VERSION 5.8 ;
BUSBITCHARS "[]" ;
DIVIDERCHAR "/" ;
UNITS
    DATABASE MICRONS 1000 ;
END UNITS

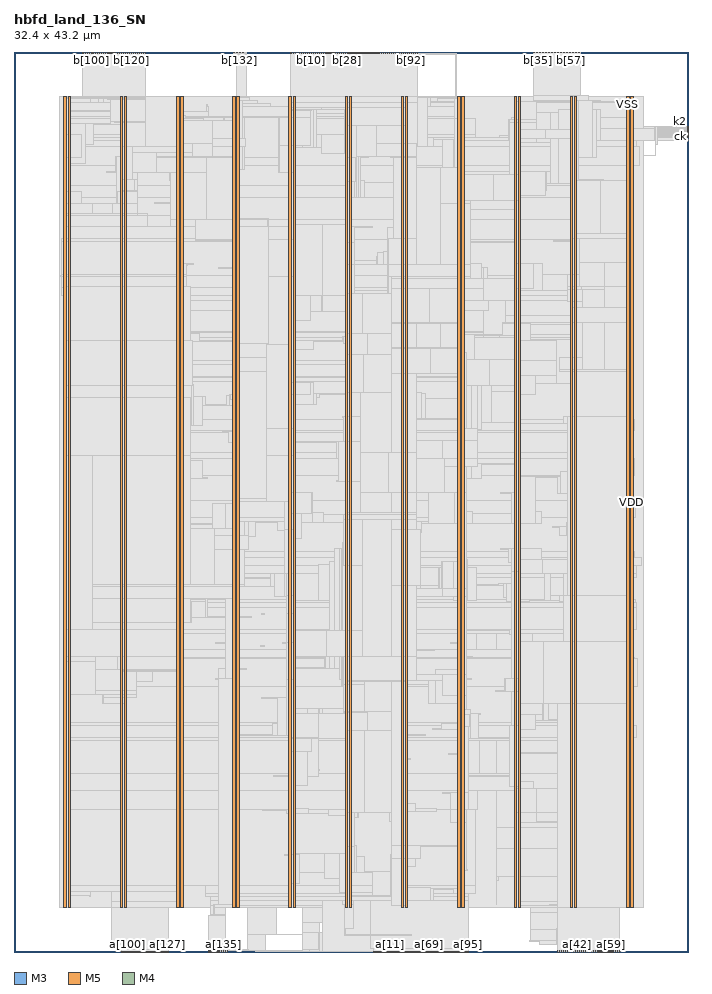
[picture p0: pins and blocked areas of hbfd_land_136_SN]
MACRO hbfd_land_136_SN
  FOREIGN hbfd_land_136_SN 0 0 ;
  CLASS BLOCK ;
  SIZE 32.4 BY 43.2 ;
  PIN a[0]
    DIRECTION INPUT ;
    USE SIGNAL ;
    PORT
      LAYER M3 ;
        RECT  17.244 0 17.262 0.037 ;
    END
  END a[0]
  PIN a[100]
    DIRECTION INPUT ;
    USE SIGNAL ;
    PORT
      LAYER M3 ;
        RECT  5.436 0 5.454 0.037 ;
    END
  END a[100]
  PIN a[101]
    DIRECTION INPUT ;
    USE SIGNAL ;
    PORT
      LAYER M3 ;
        RECT  5.508 0 5.526 0.037 ;
    END
  END a[101]
  PIN a[102]
    DIRECTION INPUT ;
    USE SIGNAL ;
    PORT
      LAYER M3 ;
        RECT  5.58 0 5.598 0.037 ;
    END
  END a[102]
  PIN a[103]
    DIRECTION INPUT ;
    USE SIGNAL ;
    PORT
      LAYER M3 ;
        RECT  5.652 0 5.67 0.037 ;
    END
  END a[103]
  PIN a[104]
    DIRECTION INPUT ;
    USE SIGNAL ;
    PORT
      LAYER M3 ;
        RECT  5.724 0 5.742 0.037 ;
    END
  END a[104]
  PIN a[105]
    DIRECTION INPUT ;
    USE SIGNAL ;
    PORT
      LAYER M3 ;
        RECT  5.796 0 5.814 0.037 ;
    END
  END a[105]
  PIN a[106]
    DIRECTION INPUT ;
    USE SIGNAL ;
    PORT
      LAYER M3 ;
        RECT  5.868 0 5.886 0.037 ;
    END
  END a[106]
  PIN a[107]
    DIRECTION INPUT ;
    USE SIGNAL ;
    PORT
      LAYER M3 ;
        RECT  5.94 0 5.958 0.037 ;
    END
  END a[107]
  PIN a[108]
    DIRECTION INPUT ;
    USE SIGNAL ;
    PORT
      LAYER M3 ;
        RECT  6.012 0 6.03 0.037 ;
    END
  END a[108]
  PIN a[109]
    DIRECTION INPUT ;
    USE SIGNAL ;
    PORT
      LAYER M3 ;
        RECT  6.084 0 6.102 0.037 ;
    END
  END a[109]
  PIN a[10]
    DIRECTION INPUT ;
    USE SIGNAL ;
    PORT
      LAYER M3 ;
        RECT  17.964 0 17.982 0.037 ;
    END
  END a[10]
  PIN a[110]
    DIRECTION INPUT ;
    USE SIGNAL ;
    PORT
      LAYER M3 ;
        RECT  6.156 0 6.174 0.037 ;
    END
  END a[110]
  PIN a[111]
    DIRECTION INPUT ;
    USE SIGNAL ;
    PORT
      LAYER M3 ;
        RECT  6.228 0 6.246 0.037 ;
    END
  END a[111]
  PIN a[112]
    DIRECTION INPUT ;
    USE SIGNAL ;
    PORT
      LAYER M3 ;
        RECT  6.3 0 6.318 0.037 ;
    END
  END a[112]
  PIN a[113]
    DIRECTION INPUT ;
    USE SIGNAL ;
    PORT
      LAYER M3 ;
        RECT  6.372 0 6.39 0.037 ;
    END
  END a[113]
  PIN a[114]
    DIRECTION INPUT ;
    USE SIGNAL ;
    PORT
      LAYER M3 ;
        RECT  6.444 0 6.462 0.037 ;
    END
  END a[114]
  PIN a[115]
    DIRECTION INPUT ;
    USE SIGNAL ;
    PORT
      LAYER M3 ;
        RECT  6.516 0 6.534 0.037 ;
    END
  END a[115]
  PIN a[116]
    DIRECTION INPUT ;
    USE SIGNAL ;
    PORT
      LAYER M3 ;
        RECT  6.588 0 6.606 0.037 ;
    END
  END a[116]
  PIN a[117]
    DIRECTION INPUT ;
    USE SIGNAL ;
    PORT
      LAYER M3 ;
        RECT  6.66 0 6.678 0.037 ;
    END
  END a[117]
  PIN a[118]
    DIRECTION INPUT ;
    USE SIGNAL ;
    PORT
      LAYER M3 ;
        RECT  6.732 0 6.75 0.037 ;
    END
  END a[118]
  PIN a[119]
    DIRECTION INPUT ;
    USE SIGNAL ;
    PORT
      LAYER M3 ;
        RECT  6.804 0 6.822 0.037 ;
    END
  END a[119]
  PIN a[11]
    DIRECTION INPUT ;
    USE SIGNAL ;
    PORT
      LAYER M3 ;
        RECT  18.036 0 18.054 0.037 ;
    END
  END a[11]
  PIN a[120]
    DIRECTION INPUT ;
    USE SIGNAL ;
    PORT
      LAYER M3 ;
        RECT  6.876 0 6.894 0.037 ;
    END
  END a[120]
  PIN a[121]
    DIRECTION INPUT ;
    USE SIGNAL ;
    PORT
      LAYER M3 ;
        RECT  6.948 0 6.966 0.037 ;
    END
  END a[121]
  PIN a[122]
    DIRECTION INPUT ;
    USE SIGNAL ;
    PORT
      LAYER M3 ;
        RECT  7.02 0 7.038 0.037 ;
    END
  END a[122]
  PIN a[123]
    DIRECTION INPUT ;
    USE SIGNAL ;
    PORT
      LAYER M3 ;
        RECT  7.092 0 7.11 0.037 ;
    END
  END a[123]
  PIN a[124]
    DIRECTION INPUT ;
    USE SIGNAL ;
    PORT
      LAYER M3 ;
        RECT  7.164 0 7.182 0.037 ;
    END
  END a[124]
  PIN a[125]
    DIRECTION INPUT ;
    USE SIGNAL ;
    PORT
      LAYER M3 ;
        RECT  7.236 0 7.254 0.037 ;
    END
  END a[125]
  PIN a[126]
    DIRECTION INPUT ;
    USE SIGNAL ;
    PORT
      LAYER M3 ;
        RECT  7.308 0 7.326 0.037 ;
    END
  END a[126]
  PIN a[127]
    DIRECTION INPUT ;
    USE SIGNAL ;
    PORT
      LAYER M3 ;
        RECT  7.38 0 7.398 0.037 ;
    END
  END a[127]
  PIN a[128]
    DIRECTION INPUT ;
    USE SIGNAL ;
    PORT
      LAYER M5 ;
        RECT  9.36 0 9.384 0.084 ;
    END
  END a[128]
  PIN a[129]
    DIRECTION INPUT ;
    USE SIGNAL ;
    PORT
      LAYER M5 ;
        RECT  9.456 0 9.48 0.084 ;
    END
  END a[129]
  PIN a[12]
    DIRECTION INPUT ;
    USE SIGNAL ;
    PORT
      LAYER M3 ;
        RECT  18.108 0 18.126 0.037 ;
    END
  END a[12]
  PIN a[130]
    DIRECTION INPUT ;
    USE SIGNAL ;
    PORT
      LAYER M5 ;
        RECT  9.552 0 9.576 0.084 ;
    END
  END a[130]
  PIN a[131]
    DIRECTION INPUT ;
    USE SIGNAL ;
    PORT
      LAYER M5 ;
        RECT  9.648 0 9.672 0.084 ;
    END
  END a[131]
  PIN a[132]
    DIRECTION INPUT ;
    USE SIGNAL ;
    PORT
      LAYER M5 ;
        RECT  9.744 0 9.768 0.084 ;
    END
  END a[132]
  PIN a[133]
    DIRECTION INPUT ;
    USE SIGNAL ;
    PORT
      LAYER M5 ;
        RECT  9.84 0 9.864 0.084 ;
    END
  END a[133]
  PIN a[134]
    DIRECTION INPUT ;
    USE SIGNAL ;
    PORT
      LAYER M5 ;
        RECT  9.936 0 9.96 0.084 ;
    END
  END a[134]
  PIN a[135]
    DIRECTION INPUT ;
    USE SIGNAL ;
    PORT
      LAYER M5 ;
        RECT  10.032 0 10.056 0.084 ;
    END
  END a[135]
  PIN a[13]
    DIRECTION INPUT ;
    USE SIGNAL ;
    PORT
      LAYER M3 ;
        RECT  18.18 0 18.198 0.037 ;
    END
  END a[13]
  PIN a[14]
    DIRECTION INPUT ;
    USE SIGNAL ;
    PORT
      LAYER M3 ;
        RECT  18.252 0 18.27 0.037 ;
    END
  END a[14]
  PIN a[15]
    DIRECTION INPUT ;
    USE SIGNAL ;
    PORT
      LAYER M3 ;
        RECT  18.324 0 18.342 0.037 ;
    END
  END a[15]
  PIN a[16]
    DIRECTION INPUT ;
    USE SIGNAL ;
    PORT
      LAYER M3 ;
        RECT  18.396 0 18.414 0.037 ;
    END
  END a[16]
  PIN a[17]
    DIRECTION INPUT ;
    USE SIGNAL ;
    PORT
      LAYER M3 ;
        RECT  18.468 0 18.486 0.037 ;
    END
  END a[17]
  PIN a[18]
    DIRECTION INPUT ;
    USE SIGNAL ;
    PORT
      LAYER M3 ;
        RECT  18.54 0 18.558 0.037 ;
    END
  END a[18]
  PIN a[19]
    DIRECTION INPUT ;
    USE SIGNAL ;
    PORT
      LAYER M3 ;
        RECT  18.612 0 18.63 0.037 ;
    END
  END a[19]
  PIN a[1]
    DIRECTION INPUT ;
    USE SIGNAL ;
    PORT
      LAYER M3 ;
        RECT  17.316 0 17.334 0.037 ;
    END
  END a[1]
  PIN a[20]
    DIRECTION INPUT ;
    USE SIGNAL ;
    PORT
      LAYER M3 ;
        RECT  18.684 0 18.702 0.037 ;
    END
  END a[20]
  PIN a[21]
    DIRECTION INPUT ;
    USE SIGNAL ;
    PORT
      LAYER M3 ;
        RECT  18.756 0 18.774 0.037 ;
    END
  END a[21]
  PIN a[22]
    DIRECTION INPUT ;
    USE SIGNAL ;
    PORT
      LAYER M3 ;
        RECT  18.828 0 18.846 0.037 ;
    END
  END a[22]
  PIN a[23]
    DIRECTION INPUT ;
    USE SIGNAL ;
    PORT
      LAYER M3 ;
        RECT  18.9 0 18.918 0.037 ;
    END
  END a[23]
  PIN a[24]
    DIRECTION INPUT ;
    USE SIGNAL ;
    PORT
      LAYER M3 ;
        RECT  18.972 0 18.99 0.037 ;
    END
  END a[24]
  PIN a[25]
    DIRECTION INPUT ;
    USE SIGNAL ;
    PORT
      LAYER M3 ;
        RECT  19.044 0 19.062 0.037 ;
    END
  END a[25]
  PIN a[26]
    DIRECTION INPUT ;
    USE SIGNAL ;
    PORT
      LAYER M3 ;
        RECT  19.116 0 19.134 0.037 ;
    END
  END a[26]
  PIN a[27]
    DIRECTION INPUT ;
    USE SIGNAL ;
    PORT
      LAYER M3 ;
        RECT  19.188 0 19.206 0.037 ;
    END
  END a[27]
  PIN a[28]
    DIRECTION INPUT ;
    USE SIGNAL ;
    PORT
      LAYER M3 ;
        RECT  19.26 0 19.278 0.037 ;
    END
  END a[28]
  PIN a[29]
    DIRECTION INPUT ;
    USE SIGNAL ;
    PORT
      LAYER M3 ;
        RECT  19.332 0 19.35 0.037 ;
    END
  END a[29]
  PIN a[2]
    DIRECTION INPUT ;
    USE SIGNAL ;
    PORT
      LAYER M3 ;
        RECT  17.388 0 17.406 0.037 ;
    END
  END a[2]
  PIN a[30]
    DIRECTION INPUT ;
    USE SIGNAL ;
    PORT
      LAYER M3 ;
        RECT  19.404 0 19.422 0.037 ;
    END
  END a[30]
  PIN a[31]
    DIRECTION INPUT ;
    USE SIGNAL ;
    PORT
      LAYER M3 ;
        RECT  19.476 0 19.494 0.037 ;
    END
  END a[31]
  PIN a[32]
    DIRECTION INPUT ;
    USE SIGNAL ;
    PORT
      LAYER M5 ;
        RECT  26.064 0 26.088 0.084 ;
    END
  END a[32]
  PIN a[33]
    DIRECTION INPUT ;
    USE SIGNAL ;
    PORT
      LAYER M5 ;
        RECT  26.16 0 26.184 0.084 ;
    END
  END a[33]
  PIN a[34]
    DIRECTION INPUT ;
    USE SIGNAL ;
    PORT
      LAYER M5 ;
        RECT  26.256 0 26.28 0.084 ;
    END
  END a[34]
  PIN a[35]
    DIRECTION INPUT ;
    USE SIGNAL ;
    PORT
      LAYER M5 ;
        RECT  26.352 0 26.376 0.084 ;
    END
  END a[35]
  PIN a[36]
    DIRECTION INPUT ;
    USE SIGNAL ;
    PORT
      LAYER M5 ;
        RECT  26.448 0 26.472 0.084 ;
    END
  END a[36]
  PIN a[37]
    DIRECTION INPUT ;
    USE SIGNAL ;
    PORT
      LAYER M5 ;
        RECT  26.544 0 26.568 0.084 ;
    END
  END a[37]
  PIN a[38]
    DIRECTION INPUT ;
    USE SIGNAL ;
    PORT
      LAYER M5 ;
        RECT  26.64 0 26.664 0.084 ;
    END
  END a[38]
  PIN a[39]
    DIRECTION INPUT ;
    USE SIGNAL ;
    PORT
      LAYER M5 ;
        RECT  26.736 0 26.76 0.084 ;
    END
  END a[39]
  PIN a[3]
    DIRECTION INPUT ;
    USE SIGNAL ;
    PORT
      LAYER M3 ;
        RECT  17.46 0 17.478 0.037 ;
    END
  END a[3]
  PIN a[40]
    DIRECTION INPUT ;
    USE SIGNAL ;
    PORT
      LAYER M5 ;
        RECT  26.832 0 26.856 0.084 ;
    END
  END a[40]
  PIN a[41]
    DIRECTION INPUT ;
    USE SIGNAL ;
    PORT
      LAYER M5 ;
        RECT  26.928 0 26.952 0.084 ;
    END
  END a[41]
  PIN a[42]
    DIRECTION INPUT ;
    USE SIGNAL ;
    PORT
      LAYER M5 ;
        RECT  27.024 0 27.048 0.084 ;
    END
  END a[42]
  PIN a[43]
    DIRECTION INPUT ;
    USE SIGNAL ;
    PORT
      LAYER M5 ;
        RECT  27.12 0 27.144 0.084 ;
    END
  END a[43]
  PIN a[44]
    DIRECTION INPUT ;
    USE SIGNAL ;
    PORT
      LAYER M5 ;
        RECT  27.216 0 27.24 0.084 ;
    END
  END a[44]
  PIN a[45]
    DIRECTION INPUT ;
    USE SIGNAL ;
    PORT
      LAYER M5 ;
        RECT  27.312 0 27.336 0.084 ;
    END
  END a[45]
  PIN a[46]
    DIRECTION INPUT ;
    USE SIGNAL ;
    PORT
      LAYER M5 ;
        RECT  27.408 0 27.432 0.084 ;
    END
  END a[46]
  PIN a[47]
    DIRECTION INPUT ;
    USE SIGNAL ;
    PORT
      LAYER M5 ;
        RECT  27.504 0 27.528 0.084 ;
    END
  END a[47]
  PIN a[48]
    DIRECTION INPUT ;
    USE SIGNAL ;
    PORT
      LAYER M5 ;
        RECT  27.6 0 27.624 0.084 ;
    END
  END a[48]
  PIN a[49]
    DIRECTION INPUT ;
    USE SIGNAL ;
    PORT
      LAYER M5 ;
        RECT  27.696 0 27.72 0.084 ;
    END
  END a[49]
  PIN a[4]
    DIRECTION INPUT ;
    USE SIGNAL ;
    PORT
      LAYER M3 ;
        RECT  17.532 0 17.55 0.037 ;
    END
  END a[4]
  PIN a[50]
    DIRECTION INPUT ;
    USE SIGNAL ;
    PORT
      LAYER M5 ;
        RECT  27.792 0 27.816 0.084 ;
    END
  END a[50]
  PIN a[51]
    DIRECTION INPUT ;
    USE SIGNAL ;
    PORT
      LAYER M5 ;
        RECT  27.888 0 27.912 0.084 ;
    END
  END a[51]
  PIN a[52]
    DIRECTION INPUT ;
    USE SIGNAL ;
    PORT
      LAYER M5 ;
        RECT  27.984 0 28.008 0.084 ;
    END
  END a[52]
  PIN a[53]
    DIRECTION INPUT ;
    USE SIGNAL ;
    PORT
      LAYER M5 ;
        RECT  28.08 0 28.104 0.084 ;
    END
  END a[53]
  PIN a[54]
    DIRECTION INPUT ;
    USE SIGNAL ;
    PORT
      LAYER M5 ;
        RECT  28.176 0 28.2 0.084 ;
    END
  END a[54]
  PIN a[55]
    DIRECTION INPUT ;
    USE SIGNAL ;
    PORT
      LAYER M5 ;
        RECT  28.272 0 28.296 0.084 ;
    END
  END a[55]
  PIN a[56]
    DIRECTION INPUT ;
    USE SIGNAL ;
    PORT
      LAYER M5 ;
        RECT  28.368 0 28.392 0.084 ;
    END
  END a[56]
  PIN a[57]
    DIRECTION INPUT ;
    USE SIGNAL ;
    PORT
      LAYER M5 ;
        RECT  28.464 0 28.488 0.084 ;
    END
  END a[57]
  PIN a[58]
    DIRECTION INPUT ;
    USE SIGNAL ;
    PORT
      LAYER M5 ;
        RECT  28.56 0 28.584 0.084 ;
    END
  END a[58]
  PIN a[59]
    DIRECTION INPUT ;
    USE SIGNAL ;
    PORT
      LAYER M5 ;
        RECT  28.656 0 28.68 0.084 ;
    END
  END a[59]
  PIN a[5]
    DIRECTION INPUT ;
    USE SIGNAL ;
    PORT
      LAYER M3 ;
        RECT  17.604 0 17.622 0.037 ;
    END
  END a[5]
  PIN a[60]
    DIRECTION INPUT ;
    USE SIGNAL ;
    PORT
      LAYER M5 ;
        RECT  28.752 0 28.776 0.084 ;
    END
  END a[60]
  PIN a[61]
    DIRECTION INPUT ;
    USE SIGNAL ;
    PORT
      LAYER M5 ;
        RECT  28.848 0 28.872 0.084 ;
    END
  END a[61]
  PIN a[62]
    DIRECTION INPUT ;
    USE SIGNAL ;
    PORT
      LAYER M5 ;
        RECT  28.944 0 28.968 0.084 ;
    END
  END a[62]
  PIN a[63]
    DIRECTION INPUT ;
    USE SIGNAL ;
    PORT
      LAYER M5 ;
        RECT  29.04 0 29.064 0.084 ;
    END
  END a[63]
  PIN a[64]
    DIRECTION INPUT ;
    USE SIGNAL ;
    PORT
      LAYER M3 ;
        RECT  19.548 0 19.566 0.037 ;
    END
  END a[64]
  PIN a[65]
    DIRECTION INPUT ;
    USE SIGNAL ;
    PORT
      LAYER M3 ;
        RECT  19.62 0 19.638 0.037 ;
    END
  END a[65]
  PIN a[66]
    DIRECTION INPUT ;
    USE SIGNAL ;
    PORT
      LAYER M3 ;
        RECT  19.692 0 19.71 0.037 ;
    END
  END a[66]
  PIN a[67]
    DIRECTION INPUT ;
    USE SIGNAL ;
    PORT
      LAYER M3 ;
        RECT  19.764 0 19.782 0.037 ;
    END
  END a[67]
  PIN a[68]
    DIRECTION INPUT ;
    USE SIGNAL ;
    PORT
      LAYER M3 ;
        RECT  19.836 0 19.854 0.037 ;
    END
  END a[68]
  PIN a[69]
    DIRECTION INPUT ;
    USE SIGNAL ;
    PORT
      LAYER M3 ;
        RECT  19.908 0 19.926 0.037 ;
    END
  END a[69]
  PIN a[6]
    DIRECTION INPUT ;
    USE SIGNAL ;
    PORT
      LAYER M3 ;
        RECT  17.676 0 17.694 0.037 ;
    END
  END a[6]
  PIN a[70]
    DIRECTION INPUT ;
    USE SIGNAL ;
    PORT
      LAYER M3 ;
        RECT  19.98 0 19.998 0.037 ;
    END
  END a[70]
  PIN a[71]
    DIRECTION INPUT ;
    USE SIGNAL ;
    PORT
      LAYER M3 ;
        RECT  20.052 0 20.07 0.037 ;
    END
  END a[71]
  PIN a[72]
    DIRECTION INPUT ;
    USE SIGNAL ;
    PORT
      LAYER M3 ;
        RECT  20.124 0 20.142 0.037 ;
    END
  END a[72]
  PIN a[73]
    DIRECTION INPUT ;
    USE SIGNAL ;
    PORT
      LAYER M3 ;
        RECT  20.196 0 20.214 0.037 ;
    END
  END a[73]
  PIN a[74]
    DIRECTION INPUT ;
    USE SIGNAL ;
    PORT
      LAYER M3 ;
        RECT  20.268 0 20.286 0.037 ;
    END
  END a[74]
  PIN a[75]
    DIRECTION INPUT ;
    USE SIGNAL ;
    PORT
      LAYER M3 ;
        RECT  20.34 0 20.358 0.037 ;
    END
  END a[75]
  PIN a[76]
    DIRECTION INPUT ;
    USE SIGNAL ;
    PORT
      LAYER M3 ;
        RECT  20.412 0 20.43 0.037 ;
    END
  END a[76]
  PIN a[77]
    DIRECTION INPUT ;
    USE SIGNAL ;
    PORT
      LAYER M3 ;
        RECT  20.484 0 20.502 0.037 ;
    END
  END a[77]
  PIN a[78]
    DIRECTION INPUT ;
    USE SIGNAL ;
    PORT
      LAYER M3 ;
        RECT  20.556 0 20.574 0.037 ;
    END
  END a[78]
  PIN a[79]
    DIRECTION INPUT ;
    USE SIGNAL ;
    PORT
      LAYER M3 ;
        RECT  20.628 0 20.646 0.037 ;
    END
  END a[79]
  PIN a[7]
    DIRECTION INPUT ;
    USE SIGNAL ;
    PORT
      LAYER M3 ;
        RECT  17.748 0 17.766 0.037 ;
    END
  END a[7]
  PIN a[80]
    DIRECTION INPUT ;
    USE SIGNAL ;
    PORT
      LAYER M3 ;
        RECT  20.7 0 20.718 0.037 ;
    END
  END a[80]
  PIN a[81]
    DIRECTION INPUT ;
    USE SIGNAL ;
    PORT
      LAYER M3 ;
        RECT  20.772 0 20.79 0.037 ;
    END
  END a[81]
  PIN a[82]
    DIRECTION INPUT ;
    USE SIGNAL ;
    PORT
      LAYER M3 ;
        RECT  20.844 0 20.862 0.037 ;
    END
  END a[82]
  PIN a[83]
    DIRECTION INPUT ;
    USE SIGNAL ;
    PORT
      LAYER M3 ;
        RECT  20.916 0 20.934 0.037 ;
    END
  END a[83]
  PIN a[84]
    DIRECTION INPUT ;
    USE SIGNAL ;
    PORT
      LAYER M3 ;
        RECT  20.988 0 21.006 0.037 ;
    END
  END a[84]
  PIN a[85]
    DIRECTION INPUT ;
    USE SIGNAL ;
    PORT
      LAYER M3 ;
        RECT  21.06 0 21.078 0.037 ;
    END
  END a[85]
  PIN a[86]
    DIRECTION INPUT ;
    USE SIGNAL ;
    PORT
      LAYER M3 ;
        RECT  21.132 0 21.15 0.037 ;
    END
  END a[86]
  PIN a[87]
    DIRECTION INPUT ;
    USE SIGNAL ;
    PORT
      LAYER M3 ;
        RECT  21.204 0 21.222 0.037 ;
    END
  END a[87]
  PIN a[88]
    DIRECTION INPUT ;
    USE SIGNAL ;
    PORT
      LAYER M3 ;
        RECT  21.276 0 21.294 0.037 ;
    END
  END a[88]
  PIN a[89]
    DIRECTION INPUT ;
    USE SIGNAL ;
    PORT
      LAYER M3 ;
        RECT  21.348 0 21.366 0.037 ;
    END
  END a[89]
  PIN a[8]
    DIRECTION INPUT ;
    USE SIGNAL ;
    PORT
      LAYER M3 ;
        RECT  17.82 0 17.838 0.037 ;
    END
  END a[8]
  PIN a[90]
    DIRECTION INPUT ;
    USE SIGNAL ;
    PORT
      LAYER M3 ;
        RECT  21.42 0 21.438 0.037 ;
    END
  END a[90]
  PIN a[91]
    DIRECTION INPUT ;
    USE SIGNAL ;
    PORT
      LAYER M3 ;
        RECT  21.492 0 21.51 0.037 ;
    END
  END a[91]
  PIN a[92]
    DIRECTION INPUT ;
    USE SIGNAL ;
    PORT
      LAYER M3 ;
        RECT  21.564 0 21.582 0.037 ;
    END
  END a[92]
  PIN a[93]
    DIRECTION INPUT ;
    USE SIGNAL ;
    PORT
      LAYER M3 ;
        RECT  21.636 0 21.654 0.037 ;
    END
  END a[93]
  PIN a[94]
    DIRECTION INPUT ;
    USE SIGNAL ;
    PORT
      LAYER M3 ;
        RECT  21.708 0 21.726 0.037 ;
    END
  END a[94]
  PIN a[95]
    DIRECTION INPUT ;
    USE SIGNAL ;
    PORT
      LAYER M3 ;
        RECT  21.78 0 21.798 0.037 ;
    END
  END a[95]
  PIN a[96]
    DIRECTION INPUT ;
    USE SIGNAL ;
    PORT
      LAYER M3 ;
        RECT  5.148 0 5.166 0.037 ;
    END
  END a[96]
  PIN a[97]
    DIRECTION INPUT ;
    USE SIGNAL ;
    PORT
      LAYER M3 ;
        RECT  5.22 0 5.238 0.037 ;
    END
  END a[97]
  PIN a[98]
    DIRECTION INPUT ;
    USE SIGNAL ;
    PORT
      LAYER M3 ;
        RECT  5.292 0 5.31 0.037 ;
    END
  END a[98]
  PIN a[99]
    DIRECTION INPUT ;
    USE SIGNAL ;
    PORT
      LAYER M3 ;
        RECT  5.364 0 5.382 0.037 ;
    END
  END a[99]
  PIN a[9]
    DIRECTION INPUT ;
    USE SIGNAL ;
    PORT
      LAYER M3 ;
        RECT  17.892 0 17.91 0.037 ;
    END
  END a[9]
  PIN b[0]
    DIRECTION OUTPUT ;
    USE SIGNAL ;
    PORT
      LAYER M5 ;
        RECT  13.296 43.116 13.32 43.2 ;
    END
  END b[0]
  PIN b[100]
    DIRECTION OUTPUT ;
    USE SIGNAL ;
    PORT
      LAYER M5 ;
        RECT  3.696 43.116 3.72 43.2 ;
    END
  END b[100]
  PIN b[101]
    DIRECTION OUTPUT ;
    USE SIGNAL ;
    PORT
      LAYER M5 ;
        RECT  3.792 43.116 3.816 43.2 ;
    END
  END b[101]
  PIN b[102]
    DIRECTION OUTPUT ;
    USE SIGNAL ;
    PORT
      LAYER M5 ;
        RECT  3.888 43.116 3.912 43.2 ;
    END
  END b[102]
  PIN b[103]
    DIRECTION OUTPUT ;
    USE SIGNAL ;
    PORT
      LAYER M5 ;
        RECT  3.984 43.116 4.008 43.2 ;
    END
  END b[103]
  PIN b[104]
    DIRECTION OUTPUT ;
    USE SIGNAL ;
    PORT
      LAYER M5 ;
        RECT  4.08 43.116 4.104 43.2 ;
    END
  END b[104]
  PIN b[105]
    DIRECTION OUTPUT ;
    USE SIGNAL ;
    PORT
      LAYER M5 ;
        RECT  4.176 43.116 4.2 43.2 ;
    END
  END b[105]
  PIN b[106]
    DIRECTION OUTPUT ;
    USE SIGNAL ;
    PORT
      LAYER M5 ;
        RECT  4.272 43.116 4.296 43.2 ;
    END
  END b[106]
  PIN b[107]
    DIRECTION OUTPUT ;
    USE SIGNAL ;
    PORT
      LAYER M5 ;
        RECT  4.368 43.116 4.392 43.2 ;
    END
  END b[107]
  PIN b[108]
    DIRECTION OUTPUT ;
    USE SIGNAL ;
    PORT
      LAYER M5 ;
        RECT  4.464 43.116 4.488 43.2 ;
    END
  END b[108]
  PIN b[109]
    DIRECTION OUTPUT ;
    USE SIGNAL ;
    PORT
      LAYER M5 ;
        RECT  4.56 43.116 4.584 43.2 ;
    END
  END b[109]
  PIN b[10]
    DIRECTION OUTPUT ;
    USE SIGNAL ;
    PORT
      LAYER M5 ;
        RECT  14.256 43.116 14.28 43.2 ;
    END
  END b[10]
  PIN b[110]
    DIRECTION OUTPUT ;
    USE SIGNAL ;
    PORT
      LAYER M5 ;
        RECT  4.656 43.116 4.68 43.2 ;
    END
  END b[110]
  PIN b[111]
    DIRECTION OUTPUT ;
    USE SIGNAL ;
    PORT
      LAYER M5 ;
        RECT  4.752 43.116 4.776 43.2 ;
    END
  END b[111]
  PIN b[112]
    DIRECTION OUTPUT ;
    USE SIGNAL ;
    PORT
      LAYER M5 ;
        RECT  4.848 43.116 4.872 43.2 ;
    END
  END b[112]
  PIN b[113]
    DIRECTION OUTPUT ;
    USE SIGNAL ;
    PORT
      LAYER M5 ;
        RECT  4.944 43.116 4.968 43.2 ;
    END
  END b[113]
  PIN b[114]
    DIRECTION OUTPUT ;
    USE SIGNAL ;
    PORT
      LAYER M5 ;
        RECT  5.04 43.116 5.064 43.2 ;
    END
  END b[114]
  PIN b[115]
    DIRECTION OUTPUT ;
    USE SIGNAL ;
    PORT
      LAYER M5 ;
        RECT  5.136 43.116 5.16 43.2 ;
    END
  END b[115]
  PIN b[116]
    DIRECTION OUTPUT ;
    USE SIGNAL ;
    PORT
      LAYER M5 ;
        RECT  5.232 43.116 5.256 43.2 ;
    END
  END b[116]
  PIN b[117]
    DIRECTION OUTPUT ;
    USE SIGNAL ;
    PORT
      LAYER M5 ;
        RECT  5.328 43.116 5.352 43.2 ;
    END
  END b[117]
  PIN b[118]
    DIRECTION OUTPUT ;
    USE SIGNAL ;
    PORT
      LAYER M5 ;
        RECT  5.424 43.116 5.448 43.2 ;
    END
  END b[118]
  PIN b[119]
    DIRECTION OUTPUT ;
    USE SIGNAL ;
    PORT
      LAYER M5 ;
        RECT  5.52 43.116 5.544 43.2 ;
    END
  END b[119]
  PIN b[11]
    DIRECTION OUTPUT ;
    USE SIGNAL ;
    PORT
      LAYER M5 ;
        RECT  14.352 43.116 14.376 43.2 ;
    END
  END b[11]
  PIN b[120]
    DIRECTION OUTPUT ;
    USE SIGNAL ;
    PORT
      LAYER M5 ;
        RECT  5.616 43.116 5.64 43.2 ;
    END
  END b[120]
  PIN b[121]
    DIRECTION OUTPUT ;
    USE SIGNAL ;
    PORT
      LAYER M5 ;
        RECT  5.712 43.116 5.736 43.2 ;
    END
  END b[121]
  PIN b[122]
    DIRECTION OUTPUT ;
    USE SIGNAL ;
    PORT
      LAYER M5 ;
        RECT  5.808 43.116 5.832 43.2 ;
    END
  END b[122]
  PIN b[123]
    DIRECTION OUTPUT ;
    USE SIGNAL ;
    PORT
      LAYER M5 ;
        RECT  5.904 43.116 5.928 43.2 ;
    END
  END b[123]
  PIN b[124]
    DIRECTION OUTPUT ;
    USE SIGNAL ;
    PORT
      LAYER M5 ;
        RECT  6 43.116 6.024 43.2 ;
    END
  END b[124]
  PIN b[125]
    DIRECTION OUTPUT ;
    USE SIGNAL ;
    PORT
      LAYER M5 ;
        RECT  6.096 43.116 6.12 43.2 ;
    END
  END b[125]
  PIN b[126]
    DIRECTION OUTPUT ;
    USE SIGNAL ;
    PORT
      LAYER M5 ;
        RECT  6.192 43.116 6.216 43.2 ;
    END
  END b[126]
  PIN b[127]
    DIRECTION OUTPUT ;
    USE SIGNAL ;
    PORT
      LAYER M5 ;
        RECT  6.288 43.116 6.312 43.2 ;
    END
  END b[127]
  PIN b[128]
    DIRECTION OUTPUT ;
    USE SIGNAL ;
    PORT
      LAYER M3 ;
        RECT  10.548 43.163 10.566 43.2 ;
    END
  END b[128]
  PIN b[129]
    DIRECTION OUTPUT ;
    USE SIGNAL ;
    PORT
      LAYER M3 ;
        RECT  10.62 43.163 10.638 43.2 ;
    END
  END b[129]
  PIN b[12]
    DIRECTION OUTPUT ;
    USE SIGNAL ;
    PORT
      LAYER M5 ;
        RECT  14.448 43.116 14.472 43.2 ;
    END
  END b[12]
  PIN b[130]
    DIRECTION OUTPUT ;
    USE SIGNAL ;
    PORT
      LAYER M3 ;
        RECT  10.692 43.163 10.71 43.2 ;
    END
  END b[130]
  PIN b[131]
    DIRECTION OUTPUT ;
    USE SIGNAL ;
    PORT
      LAYER M3 ;
        RECT  10.764 43.163 10.782 43.2 ;
    END
  END b[131]
  PIN b[132]
    DIRECTION OUTPUT ;
    USE SIGNAL ;
    PORT
      LAYER M3 ;
        RECT  10.836 43.163 10.854 43.2 ;
    END
  END b[132]
  PIN b[133]
    DIRECTION OUTPUT ;
    USE SIGNAL ;
    PORT
      LAYER M3 ;
        RECT  10.908 43.163 10.926 43.2 ;
    END
  END b[133]
  PIN b[134]
    DIRECTION OUTPUT ;
    USE SIGNAL ;
    PORT
      LAYER M3 ;
        RECT  10.98 43.163 10.998 43.2 ;
    END
  END b[134]
  PIN b[135]
    DIRECTION OUTPUT ;
    USE SIGNAL ;
    PORT
      LAYER M3 ;
        RECT  11.052 43.163 11.07 43.2 ;
    END
  END b[135]
  PIN b[13]
    DIRECTION OUTPUT ;
    USE SIGNAL ;
    PORT
      LAYER M5 ;
        RECT  14.544 43.116 14.568 43.2 ;
    END
  END b[13]
  PIN b[14]
    DIRECTION OUTPUT ;
    USE SIGNAL ;
    PORT
      LAYER M5 ;
        RECT  14.64 43.116 14.664 43.2 ;
    END
  END b[14]
  PIN b[15]
    DIRECTION OUTPUT ;
    USE SIGNAL ;
    PORT
      LAYER M5 ;
        RECT  14.736 43.116 14.76 43.2 ;
    END
  END b[15]
  PIN b[16]
    DIRECTION OUTPUT ;
    USE SIGNAL ;
    PORT
      LAYER M5 ;
        RECT  14.832 43.116 14.856 43.2 ;
    END
  END b[16]
  PIN b[17]
    DIRECTION OUTPUT ;
    USE SIGNAL ;
    PORT
      LAYER M5 ;
        RECT  14.928 43.116 14.952 43.2 ;
    END
  END b[17]
  PIN b[18]
    DIRECTION OUTPUT ;
    USE SIGNAL ;
    PORT
      LAYER M5 ;
        RECT  15.024 43.116 15.048 43.2 ;
    END
  END b[18]
  PIN b[19]
    DIRECTION OUTPUT ;
    USE SIGNAL ;
    PORT
      LAYER M5 ;
        RECT  15.12 43.116 15.144 43.2 ;
    END
  END b[19]
  PIN b[1]
    DIRECTION OUTPUT ;
    USE SIGNAL ;
    PORT
      LAYER M5 ;
        RECT  13.392 43.116 13.416 43.2 ;
    END
  END b[1]
  PIN b[20]
    DIRECTION OUTPUT ;
    USE SIGNAL ;
    PORT
      LAYER M5 ;
        RECT  15.216 43.116 15.24 43.2 ;
    END
  END b[20]
  PIN b[21]
    DIRECTION OUTPUT ;
    USE SIGNAL ;
    PORT
      LAYER M5 ;
        RECT  15.312 43.116 15.336 43.2 ;
    END
  END b[21]
  PIN b[22]
    DIRECTION OUTPUT ;
    USE SIGNAL ;
    PORT
      LAYER M5 ;
        RECT  15.408 43.116 15.432 43.2 ;
    END
  END b[22]
  PIN b[23]
    DIRECTION OUTPUT ;
    USE SIGNAL ;
    PORT
      LAYER M5 ;
        RECT  15.504 43.116 15.528 43.2 ;
    END
  END b[23]
  PIN b[24]
    DIRECTION OUTPUT ;
    USE SIGNAL ;
    PORT
      LAYER M5 ;
        RECT  15.6 43.116 15.624 43.2 ;
    END
  END b[24]
  PIN b[25]
    DIRECTION OUTPUT ;
    USE SIGNAL ;
    PORT
      LAYER M5 ;
        RECT  15.696 43.116 15.72 43.2 ;
    END
  END b[25]
  PIN b[26]
    DIRECTION OUTPUT ;
    USE SIGNAL ;
    PORT
      LAYER M5 ;
        RECT  15.792 43.116 15.816 43.2 ;
    END
  END b[26]
  PIN b[27]
    DIRECTION OUTPUT ;
    USE SIGNAL ;
    PORT
      LAYER M5 ;
        RECT  15.888 43.116 15.912 43.2 ;
    END
  END b[27]
  PIN b[28]
    DIRECTION OUTPUT ;
    USE SIGNAL ;
    PORT
      LAYER M5 ;
        RECT  15.984 43.116 16.008 43.2 ;
    END
  END b[28]
  PIN b[29]
    DIRECTION OUTPUT ;
    USE SIGNAL ;
    PORT
      LAYER M5 ;
        RECT  16.08 43.116 16.104 43.2 ;
    END
  END b[29]
  PIN b[2]
    DIRECTION OUTPUT ;
    USE SIGNAL ;
    PORT
      LAYER M5 ;
        RECT  13.488 43.116 13.512 43.2 ;
    END
  END b[2]
  PIN b[30]
    DIRECTION OUTPUT ;
    USE SIGNAL ;
    PORT
      LAYER M5 ;
        RECT  16.176 43.116 16.2 43.2 ;
    END
  END b[30]
  PIN b[31]
    DIRECTION OUTPUT ;
    USE SIGNAL ;
    PORT
      LAYER M5 ;
        RECT  16.272 43.116 16.296 43.2 ;
    END
  END b[31]
  PIN b[32]
    DIRECTION OUTPUT ;
    USE SIGNAL ;
    PORT
      LAYER M3 ;
        RECT  24.948 43.163 24.966 43.2 ;
    END
  END b[32]
  PIN b[33]
    DIRECTION OUTPUT ;
    USE SIGNAL ;
    PORT
      LAYER M3 ;
        RECT  25.02 43.163 25.038 43.2 ;
    END
  END b[33]
  PIN b[34]
    DIRECTION OUTPUT ;
    USE SIGNAL ;
    PORT
      LAYER M3 ;
        RECT  25.092 43.163 25.11 43.2 ;
    END
  END b[34]
  PIN b[35]
    DIRECTION OUTPUT ;
    USE SIGNAL ;
    PORT
      LAYER M3 ;
        RECT  25.164 43.163 25.182 43.2 ;
    END
  END b[35]
  PIN b[36]
    DIRECTION OUTPUT ;
    USE SIGNAL ;
    PORT
      LAYER M3 ;
        RECT  25.236 43.163 25.254 43.2 ;
    END
  END b[36]
  PIN b[37]
    DIRECTION OUTPUT ;
    USE SIGNAL ;
    PORT
      LAYER M3 ;
        RECT  25.308 43.163 25.326 43.2 ;
    END
  END b[37]
  PIN b[38]
    DIRECTION OUTPUT ;
    USE SIGNAL ;
    PORT
      LAYER M3 ;
        RECT  25.38 43.163 25.398 43.2 ;
    END
  END b[38]
  PIN b[39]
    DIRECTION OUTPUT ;
    USE SIGNAL ;
    PORT
      LAYER M3 ;
        RECT  25.452 43.163 25.47 43.2 ;
    END
  END b[39]
  PIN b[3]
    DIRECTION OUTPUT ;
    USE SIGNAL ;
    PORT
      LAYER M5 ;
        RECT  13.584 43.116 13.608 43.2 ;
    END
  END b[3]
  PIN b[40]
    DIRECTION OUTPUT ;
    USE SIGNAL ;
    PORT
      LAYER M3 ;
        RECT  25.524 43.163 25.542 43.2 ;
    END
  END b[40]
  PIN b[41]
    DIRECTION OUTPUT ;
    USE SIGNAL ;
    PORT
      LAYER M3 ;
        RECT  25.596 43.163 25.614 43.2 ;
    END
  END b[41]
  PIN b[42]
    DIRECTION OUTPUT ;
    USE SIGNAL ;
    PORT
      LAYER M3 ;
        RECT  25.668 43.163 25.686 43.2 ;
    END
  END b[42]
  PIN b[43]
    DIRECTION OUTPUT ;
    USE SIGNAL ;
    PORT
      LAYER M3 ;
        RECT  25.74 43.163 25.758 43.2 ;
    END
  END b[43]
  PIN b[44]
    DIRECTION OUTPUT ;
    USE SIGNAL ;
    PORT
      LAYER M3 ;
        RECT  25.812 43.163 25.83 43.2 ;
    END
  END b[44]
  PIN b[45]
    DIRECTION OUTPUT ;
    USE SIGNAL ;
    PORT
      LAYER M3 ;
        RECT  25.884 43.163 25.902 43.2 ;
    END
  END b[45]
  PIN b[46]
    DIRECTION OUTPUT ;
    USE SIGNAL ;
    PORT
      LAYER M3 ;
        RECT  25.956 43.163 25.974 43.2 ;
    END
  END b[46]
  PIN b[47]
    DIRECTION OUTPUT ;
    USE SIGNAL ;
    PORT
      LAYER M3 ;
        RECT  26.028 43.163 26.046 43.2 ;
    END
  END b[47]
  PIN b[48]
    DIRECTION OUTPUT ;
    USE SIGNAL ;
    PORT
      LAYER M3 ;
        RECT  26.1 43.163 26.118 43.2 ;
    END
  END b[48]
  PIN b[49]
    DIRECTION OUTPUT ;
    USE SIGNAL ;
    PORT
      LAYER M3 ;
        RECT  26.172 43.163 26.19 43.2 ;
    END
  END b[49]
  PIN b[4]
    DIRECTION OUTPUT ;
    USE SIGNAL ;
    PORT
      LAYER M5 ;
        RECT  13.68 43.116 13.704 43.2 ;
    END
  END b[4]
  PIN b[50]
    DIRECTION OUTPUT ;
    USE SIGNAL ;
    PORT
      LAYER M3 ;
        RECT  26.244 43.163 26.262 43.2 ;
    END
  END b[50]
  PIN b[51]
    DIRECTION OUTPUT ;
    USE SIGNAL ;
    PORT
      LAYER M3 ;
        RECT  26.316 43.163 26.334 43.2 ;
    END
  END b[51]
  PIN b[52]
    DIRECTION OUTPUT ;
    USE SIGNAL ;
    PORT
      LAYER M3 ;
        RECT  26.388 43.163 26.406 43.2 ;
    END
  END b[52]
  PIN b[53]
    DIRECTION OUTPUT ;
    USE SIGNAL ;
    PORT
      LAYER M3 ;
        RECT  26.46 43.163 26.478 43.2 ;
    END
  END b[53]
  PIN b[54]
    DIRECTION OUTPUT ;
    USE SIGNAL ;
    PORT
      LAYER M3 ;
        RECT  26.532 43.163 26.55 43.2 ;
    END
  END b[54]
  PIN b[55]
    DIRECTION OUTPUT ;
    USE SIGNAL ;
    PORT
      LAYER M3 ;
        RECT  26.604 43.163 26.622 43.2 ;
    END
  END b[55]
  PIN b[56]
    DIRECTION OUTPUT ;
    USE SIGNAL ;
    PORT
      LAYER M3 ;
        RECT  26.676 43.163 26.694 43.2 ;
    END
  END b[56]
  PIN b[57]
    DIRECTION OUTPUT ;
    USE SIGNAL ;
    PORT
      LAYER M3 ;
        RECT  26.748 43.163 26.766 43.2 ;
    END
  END b[57]
  PIN b[58]
    DIRECTION OUTPUT ;
    USE SIGNAL ;
    PORT
      LAYER M3 ;
        RECT  26.82 43.163 26.838 43.2 ;
    END
  END b[58]
  PIN b[59]
    DIRECTION OUTPUT ;
    USE SIGNAL ;
    PORT
      LAYER M3 ;
        RECT  26.892 43.163 26.91 43.2 ;
    END
  END b[59]
  PIN b[5]
    DIRECTION OUTPUT ;
    USE SIGNAL ;
    PORT
      LAYER M5 ;
        RECT  13.776 43.116 13.8 43.2 ;
    END
  END b[5]
  PIN b[60]
    DIRECTION OUTPUT ;
    USE SIGNAL ;
    PORT
      LAYER M3 ;
        RECT  26.964 43.163 26.982 43.2 ;
    END
  END b[60]
  PIN b[61]
    DIRECTION OUTPUT ;
    USE SIGNAL ;
    PORT
      LAYER M3 ;
        RECT  27.036 43.163 27.054 43.2 ;
    END
  END b[61]
  PIN b[62]
    DIRECTION OUTPUT ;
    USE SIGNAL ;
    PORT
      LAYER M3 ;
        RECT  27.108 43.163 27.126 43.2 ;
    END
  END b[62]
  PIN b[63]
    DIRECTION OUTPUT ;
    USE SIGNAL ;
    PORT
      LAYER M3 ;
        RECT  27.18 43.163 27.198 43.2 ;
    END
  END b[63]
  PIN b[64]
    DIRECTION OUTPUT ;
    USE SIGNAL ;
    PORT
      LAYER M5 ;
        RECT  16.368 43.116 16.392 43.2 ;
    END
  END b[64]
  PIN b[65]
    DIRECTION OUTPUT ;
    USE SIGNAL ;
    PORT
      LAYER M5 ;
        RECT  16.464 43.116 16.488 43.2 ;
    END
  END b[65]
  PIN b[66]
    DIRECTION OUTPUT ;
    USE SIGNAL ;
    PORT
      LAYER M5 ;
        RECT  16.56 43.116 16.584 43.2 ;
    END
  END b[66]
  PIN b[67]
    DIRECTION OUTPUT ;
    USE SIGNAL ;
    PORT
      LAYER M5 ;
        RECT  16.656 43.116 16.68 43.2 ;
    END
  END b[67]
  PIN b[68]
    DIRECTION OUTPUT ;
    USE SIGNAL ;
    PORT
      LAYER M5 ;
        RECT  16.752 43.116 16.776 43.2 ;
    END
  END b[68]
  PIN b[69]
    DIRECTION OUTPUT ;
    USE SIGNAL ;
    PORT
      LAYER M5 ;
        RECT  16.848 43.116 16.872 43.2 ;
    END
  END b[69]
  PIN b[6]
    DIRECTION OUTPUT ;
    USE SIGNAL ;
    PORT
      LAYER M5 ;
        RECT  13.872 43.116 13.896 43.2 ;
    END
  END b[6]
  PIN b[70]
    DIRECTION OUTPUT ;
    USE SIGNAL ;
    PORT
      LAYER M5 ;
        RECT  16.944 43.116 16.968 43.2 ;
    END
  END b[70]
  PIN b[71]
    DIRECTION OUTPUT ;
    USE SIGNAL ;
    PORT
      LAYER M5 ;
        RECT  17.04 43.116 17.064 43.2 ;
    END
  END b[71]
  PIN b[72]
    DIRECTION OUTPUT ;
    USE SIGNAL ;
    PORT
      LAYER M5 ;
        RECT  17.136 43.116 17.16 43.2 ;
    END
  END b[72]
  PIN b[73]
    DIRECTION OUTPUT ;
    USE SIGNAL ;
    PORT
      LAYER M5 ;
        RECT  17.232 43.116 17.256 43.2 ;
    END
  END b[73]
  PIN b[74]
    DIRECTION OUTPUT ;
    USE SIGNAL ;
    PORT
      LAYER M5 ;
        RECT  17.328 43.116 17.352 43.2 ;
    END
  END b[74]
  PIN b[75]
    DIRECTION OUTPUT ;
    USE SIGNAL ;
    PORT
      LAYER M5 ;
        RECT  17.424 43.116 17.448 43.2 ;
    END
  END b[75]
  PIN b[76]
    DIRECTION OUTPUT ;
    USE SIGNAL ;
    PORT
      LAYER M5 ;
        RECT  17.52 43.116 17.544 43.2 ;
    END
  END b[76]
  PIN b[77]
    DIRECTION OUTPUT ;
    USE SIGNAL ;
    PORT
      LAYER M5 ;
        RECT  17.616 43.116 17.64 43.2 ;
    END
  END b[77]
  PIN b[78]
    DIRECTION OUTPUT ;
    USE SIGNAL ;
    PORT
      LAYER M5 ;
        RECT  17.712 43.116 17.736 43.2 ;
    END
  END b[78]
  PIN b[79]
    DIRECTION OUTPUT ;
    USE SIGNAL ;
    PORT
      LAYER M5 ;
        RECT  17.808 43.116 17.832 43.2 ;
    END
  END b[79]
  PIN b[7]
    DIRECTION OUTPUT ;
    USE SIGNAL ;
    PORT
      LAYER M5 ;
        RECT  13.968 43.116 13.992 43.2 ;
    END
  END b[7]
  PIN b[80]
    DIRECTION OUTPUT ;
    USE SIGNAL ;
    PORT
      LAYER M5 ;
        RECT  17.904 43.116 17.928 43.2 ;
    END
  END b[80]
  PIN b[81]
    DIRECTION OUTPUT ;
    USE SIGNAL ;
    PORT
      LAYER M5 ;
        RECT  18 43.116 18.024 43.2 ;
    END
  END b[81]
  PIN b[82]
    DIRECTION OUTPUT ;
    USE SIGNAL ;
    PORT
      LAYER M5 ;
        RECT  18.096 43.116 18.12 43.2 ;
    END
  END b[82]
  PIN b[83]
    DIRECTION OUTPUT ;
    USE SIGNAL ;
    PORT
      LAYER M5 ;
        RECT  18.192 43.116 18.216 43.2 ;
    END
  END b[83]
  PIN b[84]
    DIRECTION OUTPUT ;
    USE SIGNAL ;
    PORT
      LAYER M5 ;
        RECT  18.288 43.116 18.312 43.2 ;
    END
  END b[84]
  PIN b[85]
    DIRECTION OUTPUT ;
    USE SIGNAL ;
    PORT
      LAYER M5 ;
        RECT  18.384 43.116 18.408 43.2 ;
    END
  END b[85]
  PIN b[86]
    DIRECTION OUTPUT ;
    USE SIGNAL ;
    PORT
      LAYER M5 ;
        RECT  18.48 43.116 18.504 43.2 ;
    END
  END b[86]
  PIN b[87]
    DIRECTION OUTPUT ;
    USE SIGNAL ;
    PORT
      LAYER M5 ;
        RECT  18.576 43.116 18.6 43.2 ;
    END
  END b[87]
  PIN b[88]
    DIRECTION OUTPUT ;
    USE SIGNAL ;
    PORT
      LAYER M5 ;
        RECT  18.672 43.116 18.696 43.2 ;
    END
  END b[88]
  PIN b[89]
    DIRECTION OUTPUT ;
    USE SIGNAL ;
    PORT
      LAYER M5 ;
        RECT  18.768 43.116 18.792 43.2 ;
    END
  END b[89]
  PIN b[8]
    DIRECTION OUTPUT ;
    USE SIGNAL ;
    PORT
      LAYER M5 ;
        RECT  14.064 43.116 14.088 43.2 ;
    END
  END b[8]
  PIN b[90]
    DIRECTION OUTPUT ;
    USE SIGNAL ;
    PORT
      LAYER M5 ;
        RECT  18.864 43.116 18.888 43.2 ;
    END
  END b[90]
  PIN b[91]
    DIRECTION OUTPUT ;
    USE SIGNAL ;
    PORT
      LAYER M5 ;
        RECT  18.96 43.116 18.984 43.2 ;
    END
  END b[91]
  PIN b[92]
    DIRECTION OUTPUT ;
    USE SIGNAL ;
    PORT
      LAYER M5 ;
        RECT  19.056 43.116 19.08 43.2 ;
    END
  END b[92]
  PIN b[93]
    DIRECTION OUTPUT ;
    USE SIGNAL ;
    PORT
      LAYER M5 ;
        RECT  19.152 43.116 19.176 43.2 ;
    END
  END b[93]
  PIN b[94]
    DIRECTION OUTPUT ;
    USE SIGNAL ;
    PORT
      LAYER M5 ;
        RECT  19.248 43.116 19.272 43.2 ;
    END
  END b[94]
  PIN b[95]
    DIRECTION OUTPUT ;
    USE SIGNAL ;
    PORT
      LAYER M5 ;
        RECT  19.344 43.116 19.368 43.2 ;
    END
  END b[95]
  PIN b[96]
    DIRECTION OUTPUT ;
    USE SIGNAL ;
    PORT
      LAYER M5 ;
        RECT  3.312 43.116 3.336 43.2 ;
    END
  END b[96]
  PIN b[97]
    DIRECTION OUTPUT ;
    USE SIGNAL ;
    PORT
      LAYER M5 ;
        RECT  3.408 43.116 3.432 43.2 ;
    END
  END b[97]
  PIN b[98]
    DIRECTION OUTPUT ;
    USE SIGNAL ;
    PORT
      LAYER M5 ;
        RECT  3.504 43.116 3.528 43.2 ;
    END
  END b[98]
  PIN b[99]
    DIRECTION OUTPUT ;
    USE SIGNAL ;
    PORT
      LAYER M5 ;
        RECT  3.6 43.116 3.624 43.2 ;
    END
  END b[99]
  PIN b[9]
    DIRECTION OUTPUT ;
    USE SIGNAL ;
    PORT
      LAYER M5 ;
        RECT  14.16 43.116 14.184 43.2 ;
    END
  END b[9]
  PIN ck
    DIRECTION INPUT ;
    USE SIGNAL ;
    PORT
      LAYER M4 ;
        RECT  32.316 39.12 32.4 39.144 ;
    END
  END ck
  PIN ckf
    DIRECTION INPUT ;
    USE SIGNAL ;
    PORT
      LAYER M5 ;
        RECT  10.128 0 10.152 0.084 ;
    END
  END ckf
  PIN ea
    DIRECTION INPUT ;
    USE SIGNAL ;
    PORT
      LAYER M5 ;
        RECT  10.224 0 10.248 0.084 ;
    END
  END ea
  PIN fault
    DIRECTION OUTPUT ;
    USE SIGNAL ;
    PORT
      LAYER M4 ;
        RECT  32.316 39.216 32.4 39.24 ;
    END
  END fault
  PIN k0
    DIRECTION INPUT ;
    USE SIGNAL ;
    PORT
      LAYER M4 ;
        RECT  32.316 39.312 32.4 39.336 ;
    END
  END k0
  PIN k1
    DIRECTION INPUT ;
    USE SIGNAL ;
    PORT
      LAYER M4 ;
        RECT  32.316 39.408 32.4 39.432 ;
    END
  END k1
  PIN k2
    DIRECTION INPUT ;
    USE SIGNAL ;
    PORT
      LAYER M4 ;
        RECT  32.316 39.504 32.4 39.528 ;
    END
  END k2
  PIN rs
    DIRECTION INPUT ;
    USE SIGNAL ;
    PORT
      LAYER M4 ;
        RECT  32.316 39.6 32.4 39.624 ;
    END
  END rs
  PIN VDD
    DIRECTION INOUT ;
    USE POWER ;
    PORT
      LAYER M5 ;
        RECT  29.592 2.151 29.712 41.049 ;
        RECT  26.892 2.151 27.012 41.049 ;
        RECT  24.192 2.151 24.312 41.049 ;
        RECT  21.492 2.151 21.612 41.049 ;
        RECT  18.792 2.151 18.912 41.049 ;
        RECT  16.092 2.151 16.212 41.049 ;
        RECT  13.392 2.151 13.512 41.049 ;
        RECT  10.692 2.151 10.812 41.049 ;
        RECT  7.992 2.151 8.112 41.049 ;
        RECT  5.292 2.151 5.412 41.049 ;
        RECT  2.592 2.151 2.712 41.049 ;
    END
  END VDD
  PIN VSS
    DIRECTION INOUT ;
    USE GROUND ;
    PORT
      LAYER M5 ;
        RECT  29.4 2.137 29.52 41.063 ;
        RECT  26.7 2.137 26.82 41.063 ;
        RECT  24 2.137 24.12 41.063 ;
        RECT  21.3 2.137 21.42 41.063 ;
        RECT  18.6 2.137 18.72 41.063 ;
        RECT  15.9 2.137 16.02 41.063 ;
        RECT  13.2 2.137 13.32 41.063 ;
        RECT  10.5 2.137 10.62 41.063 ;
        RECT  7.8 2.137 7.92 41.063 ;
        RECT  5.1 2.137 5.22 41.063 ;
        RECT  2.4 2.137 2.52 41.063 ;
    END
  END VSS
  # OT_OBS_CLOSED layer=M5 d_um=1.536 added=79
  OBS
    LAYER RVTN ;
     RECT  2.16 2.16 30.24 2.295 ;
     RECT  2.16 2.565 30.24 2.835 ;
     RECT  2.16 3.105 30.24 3.375 ;
     RECT  2.16 3.645 30.24 3.915 ;
     RECT  2.16 4.185 30.24 4.455 ;
     RECT  2.16 4.725 30.24 4.995 ;
     RECT  2.16 5.265 30.24 5.535 ;
     RECT  2.16 5.805 30.24 6.075 ;
     RECT  2.16 6.345 30.24 6.615 ;
     RECT  2.16 6.885 30.24 7.155 ;
     RECT  2.16 7.425 30.24 7.695 ;
     RECT  2.16 7.965 30.24 8.235 ;
     RECT  2.16 8.505 30.24 8.775 ;
     RECT  2.16 9.045 30.24 9.315 ;
     RECT  2.16 9.585 30.24 9.855 ;
     RECT  2.16 10.125 30.24 10.395 ;
     RECT  2.16 10.665 30.24 10.935 ;
     RECT  2.16 11.205 30.24 11.475 ;
     RECT  2.16 11.745 30.24 12.015 ;
     RECT  2.16 12.285 30.24 12.555 ;
     RECT  2.16 12.825 30.24 13.095 ;
     RECT  2.16 13.365 30.24 13.635 ;
     RECT  2.16 13.905 30.24 14.175 ;
     RECT  2.16 14.445 30.24 14.715 ;
     RECT  2.16 14.985 30.24 15.255 ;
     RECT  2.16 15.525 30.24 15.795 ;
     RECT  2.16 16.065 30.24 16.335 ;
     RECT  2.16 16.605 30.24 16.875 ;
     RECT  2.16 17.145 30.24 17.415 ;
     RECT  2.16 17.685 30.24 17.955 ;
     RECT  2.16 18.225 30.24 18.495 ;
     RECT  2.16 18.765 30.24 19.035 ;
     RECT  2.16 19.305 30.24 19.575 ;
     RECT  2.16 19.845 30.24 20.115 ;
     RECT  2.16 20.385 30.24 20.655 ;
     RECT  2.16 20.925 30.24 21.195 ;
     RECT  2.16 21.465 30.24 21.735 ;
     RECT  2.16 22.005 30.24 22.275 ;
     RECT  2.16 22.545 30.24 22.815 ;
     RECT  2.16 23.085 30.24 23.355 ;
     RECT  2.16 23.625 30.24 23.895 ;
     RECT  2.16 24.165 30.24 24.435 ;
     RECT  2.16 24.705 30.24 24.975 ;
     RECT  2.16 25.245 30.24 25.515 ;
     RECT  2.16 25.785 30.24 26.055 ;
     RECT  2.16 26.325 30.24 26.595 ;
     RECT  2.16 26.865 30.24 27.135 ;
     RECT  2.16 27.405 30.24 27.675 ;
     RECT  2.16 27.945 30.24 28.215 ;
     RECT  2.16 28.485 30.24 28.755 ;
     RECT  2.16 29.025 30.24 29.295 ;
     RECT  2.16 29.565 30.24 29.835 ;
     RECT  2.16 30.105 30.24 30.375 ;
     RECT  2.16 30.645 30.24 30.915 ;
     RECT  2.16 31.185 30.24 31.455 ;
     RECT  2.16 31.725 30.24 31.995 ;
     RECT  2.16 32.265 30.24 32.535 ;
     RECT  2.16 32.805 30.24 33.075 ;
     RECT  2.16 33.345 30.24 33.615 ;
     RECT  2.16 33.885 30.24 34.155 ;
     RECT  2.16 34.425 30.24 34.695 ;
     RECT  2.16 34.965 30.24 35.235 ;
     RECT  2.16 35.505 30.24 35.775 ;
     RECT  2.16 36.045 30.24 36.315 ;
     RECT  2.16 36.585 30.24 36.855 ;
     RECT  2.16 37.125 30.24 37.395 ;
     RECT  2.16 37.665 30.24 37.935 ;
     RECT  2.16 38.205 30.24 38.475 ;
     RECT  2.16 38.745 30.24 39.015 ;
     RECT  2.16 39.285 30.24 39.555 ;
     RECT  2.16 39.825 30.24 40.095 ;
     RECT  2.16 40.365 30.24 40.635 ;
     RECT  2.16 40.905 30.24 41.04 ;
    LAYER RVTP ;
     RECT  2.16 2.295 30.24 2.565 ;
     RECT  2.16 2.835 30.24 3.105 ;
     RECT  2.16 3.375 30.24 3.645 ;
     RECT  2.16 3.915 30.24 4.185 ;
     RECT  2.16 4.455 30.24 4.725 ;
     RECT  2.16 4.995 30.24 5.265 ;
     RECT  2.16 5.535 30.24 5.805 ;
     RECT  2.16 6.075 30.24 6.345 ;
     RECT  2.16 6.615 30.24 6.885 ;
     RECT  2.16 7.155 30.24 7.425 ;
     RECT  2.16 7.695 30.24 7.965 ;
     RECT  2.16 8.235 30.24 8.505 ;
     RECT  2.16 8.775 30.24 9.045 ;
     RECT  2.16 9.315 30.24 9.585 ;
     RECT  2.16 9.855 30.24 10.125 ;
     RECT  2.16 10.395 30.24 10.665 ;
     RECT  2.16 10.935 30.24 11.205 ;
     RECT  2.16 11.475 30.24 11.745 ;
     RECT  2.16 12.015 30.24 12.285 ;
     RECT  2.16 12.555 30.24 12.825 ;
     RECT  2.16 13.095 30.24 13.365 ;
     RECT  2.16 13.635 30.24 13.905 ;
     RECT  2.16 14.175 30.24 14.445 ;
     RECT  2.16 14.715 30.24 14.985 ;
     RECT  2.16 15.255 30.24 15.525 ;
     RECT  2.16 15.795 30.24 16.065 ;
     RECT  2.16 16.335 30.24 16.605 ;
     RECT  2.16 16.875 30.24 17.145 ;
     RECT  2.16 17.415 30.24 17.685 ;
     RECT  2.16 17.955 30.24 18.225 ;
     RECT  2.16 18.495 30.24 18.765 ;
     RECT  2.16 19.035 30.24 19.305 ;
     RECT  2.16 19.575 30.24 19.845 ;
     RECT  2.16 20.115 30.24 20.385 ;
     RECT  2.16 20.655 30.24 20.925 ;
     RECT  2.16 21.195 30.24 21.465 ;
     RECT  2.16 21.735 30.24 22.005 ;
     RECT  2.16 22.275 30.24 22.545 ;
     RECT  2.16 22.815 30.24 23.085 ;
     RECT  2.16 23.355 30.24 23.625 ;
     RECT  2.16 23.895 30.24 24.165 ;
     RECT  2.16 24.435 30.24 24.705 ;
     RECT  2.16 24.975 30.24 25.245 ;
     RECT  2.16 25.515 30.24 25.785 ;
     RECT  2.16 26.055 30.24 26.325 ;
     RECT  2.16 26.595 30.24 26.865 ;
     RECT  2.16 27.135 30.24 27.405 ;
     RECT  2.16 27.675 30.24 27.945 ;
     RECT  2.16 28.215 30.24 28.485 ;
     RECT  2.16 28.755 30.24 29.025 ;
     RECT  2.16 29.295 30.24 29.565 ;
     RECT  2.16 29.835 30.24 30.105 ;
     RECT  2.16 30.375 30.24 30.645 ;
     RECT  2.16 30.915 30.24 31.185 ;
     RECT  2.16 31.455 30.24 31.725 ;
     RECT  2.16 31.995 30.24 32.265 ;
     RECT  2.16 32.535 30.24 32.805 ;
     RECT  2.16 33.075 30.24 33.345 ;
     RECT  2.16 33.615 30.24 33.885 ;
     RECT  2.16 34.155 30.24 34.425 ;
     RECT  2.16 34.695 30.24 34.965 ;
     RECT  2.16 35.235 30.24 35.505 ;
     RECT  2.16 35.775 30.24 36.045 ;
     RECT  2.16 36.315 30.24 36.585 ;
     RECT  2.16 36.855 30.24 37.125 ;
     RECT  2.16 37.395 30.24 37.665 ;
     RECT  2.16 37.935 30.24 38.205 ;
     RECT  2.16 38.475 30.24 38.745 ;
     RECT  2.16 39.015 30.24 39.285 ;
     RECT  2.16 39.555 30.24 39.825 ;
     RECT  2.16 40.095 30.24 40.365 ;
     RECT  2.16 40.635 30.24 40.905 ;
    LAYER M1 ;
     RECT  2.16 2.151 30.24 41.049 ;
    LAYER M2 ;
     RECT  2.16 2.151 5.071 41.049 ;
     RECT  4.675 0.108 5.143 0.126 ;
     RECT  5.071 2.106 5.215 41.049 ;
     RECT  5.215 2.034 5.351 41.049 ;
     RECT  5.143 0.036 5.387 0.126 ;
     RECT  5.387 0.036 6.871 0.054 ;
     RECT  6.871 0.036 7.087 0.126 ;
     RECT  7.087 0.036 7.151 0.198 ;
     RECT  7.151 0.108 7.259 0.198 ;
     RECT  7.259 0.108 7.367 0.126 ;
     RECT  10.543 43.146 10.615 43.164 ;
     RECT  10.615 43.074 10.823 43.164 ;
     RECT  10.823 43.146 11.147 43.164 ;
     RECT  11.587 0.036 12.055 0.054 ;
     RECT  12.055 0.036 13.855 0.09 ;
     RECT  12.559 0.846 13.855 0.864 ;
     RECT  13.855 0.036 14.179 0.864 ;
     RECT  14.179 0.036 14.647 0.9 ;
     RECT  14.647 0.036 14.791 0.936 ;
     RECT  5.351 2.151 14.791 41.049 ;
     RECT  14.791 0.036 17.627 41.049 ;
     RECT  17.627 0.108 18.563 41.049 ;
     RECT  18.563 0.108 18.571 0.198 ;
     RECT  18.563 1.152 18.635 41.049 ;
     RECT  18.635 2.106 18.923 41.049 ;
     RECT  18.571 0.036 18.959 0.198 ;
     RECT  18.959 0.108 18.995 0.198 ;
     RECT  18.995 0.18 19.363 0.198 ;
     RECT  18.635 1.152 19.391 1.17 ;
     RECT  19.363 0.18 20.011 0.279 ;
     RECT  20.011 0.036 20.147 0.279 ;
     RECT  20.147 0.261 20.795 0.279 ;
     RECT  21.235 0.18 21.343 0.198 ;
     RECT  21.343 0.036 21.551 0.198 ;
     RECT  21.551 0.036 21.659 0.126 ;
     RECT  25.123 43.146 25.159 43.164 ;
     RECT  25.159 43.074 25.259 43.164 ;
     RECT  25.259 43.146 26.095 43.164 ;
     RECT  26.095 43.074 26.195 43.164 ;
     RECT  18.923 2.151 26.743 41.049 ;
     RECT  26.195 43.146 27.095 43.164 ;
     RECT  26.743 2.151 27.563 41.13 ;
     RECT  27.563 2.151 30.24 41.049 ;
     RECT  30.24 39.096 30.767 39.618 ;
     RECT  30.24 38.214 30.803 38.232 ;
     RECT  30.767 39.096 30.803 39.114 ;
    LAYER M3 ;
     RECT  11.592 0.031 11.61 0.067 ;
     RECT  11.592 0.067 12.078 0.091 ;
     RECT  5.166 0.012 5.22 0.037 ;
     RECT  5.238 0.012 5.292 0.037 ;
     RECT  5.31 0.012 5.364 0.037 ;
     RECT  5.382 0.012 5.436 0.037 ;
     RECT  5.454 0.012 5.508 0.037 ;
     RECT  5.526 0.012 5.58 0.037 ;
     RECT  5.598 0.012 5.652 0.037 ;
     RECT  5.67 0.012 5.724 0.037 ;
     RECT  5.742 0.012 5.796 0.037 ;
     RECT  5.814 0.012 5.868 0.037 ;
     RECT  5.886 0.012 5.94 0.037 ;
     RECT  5.958 0.012 6.012 0.037 ;
     RECT  6.03 0.012 6.084 0.037 ;
     RECT  6.102 0.012 6.156 0.037 ;
     RECT  6.174 0.012 6.228 0.037 ;
     RECT  6.246 0.012 6.3 0.037 ;
     RECT  6.318 0.012 6.372 0.037 ;
     RECT  6.39 0.012 6.444 0.037 ;
     RECT  6.462 0.012 6.516 0.037 ;
     RECT  6.534 0.012 6.588 0.037 ;
     RECT  6.606 0.012 6.66 0.037 ;
     RECT  6.678 0.012 6.732 0.037 ;
     RECT  6.75 0.012 6.804 0.037 ;
     RECT  6.822 0.012 6.876 0.037 ;
     RECT  6.894 0.012 6.948 0.037 ;
     RECT  6.966 0.012 7.02 0.037 ;
     RECT  7.038 0.012 7.092 0.037 ;
     RECT  7.11 0.012 7.164 0.037 ;
     RECT  7.182 0.012 7.236 0.037 ;
     RECT  7.254 0.012 7.308 0.037 ;
     RECT  7.326 0.012 7.38 0.037 ;
     RECT  5.148 0.037 7.398 0.103 ;
     RECT  14.58 0.103 14.598 0.139 ;
     RECT  17.262 0.012 17.316 0.037 ;
     RECT  17.334 0.012 17.388 0.037 ;
     RECT  17.406 0.012 17.46 0.037 ;
     RECT  17.478 0.012 17.532 0.037 ;
     RECT  17.55 0.012 17.604 0.037 ;
     RECT  17.622 0.012 17.676 0.037 ;
     RECT  17.694 0.012 17.748 0.037 ;
     RECT  17.766 0.012 17.82 0.037 ;
     RECT  17.838 0.012 17.892 0.037 ;
     RECT  17.91 0.012 17.964 0.037 ;
     RECT  17.982 0.012 18.036 0.037 ;
     RECT  18.054 0.012 18.108 0.037 ;
     RECT  18.126 0.012 18.18 0.037 ;
     RECT  18.198 0.012 18.252 0.037 ;
     RECT  18.27 0.012 18.324 0.037 ;
     RECT  18.342 0.012 18.396 0.037 ;
     RECT  18.414 0.012 18.468 0.037 ;
     RECT  18.486 0.012 18.54 0.037 ;
     RECT  18.558 0.012 18.612 0.037 ;
     RECT  18.63 0.012 18.684 0.037 ;
     RECT  18.702 0.012 18.756 0.037 ;
     RECT  18.774 0.012 18.828 0.037 ;
     RECT  18.846 0.012 18.9 0.037 ;
     RECT  18.918 0.012 18.972 0.037 ;
     RECT  18.99 0.012 19.044 0.037 ;
     RECT  19.062 0.012 19.116 0.037 ;
     RECT  19.134 0.012 19.188 0.037 ;
     RECT  19.206 0.012 19.26 0.037 ;
     RECT  19.278 0.012 19.332 0.037 ;
     RECT  19.35 0.012 19.404 0.037 ;
     RECT  19.422 0.012 19.476 0.037 ;
     RECT  19.494 0.012 19.548 0.037 ;
     RECT  19.566 0.012 19.62 0.037 ;
     RECT  19.638 0.012 19.692 0.037 ;
     RECT  19.71 0.012 19.764 0.037 ;
     RECT  19.782 0.012 19.836 0.037 ;
     RECT  19.854 0.012 19.908 0.037 ;
     RECT  19.926 0.012 19.98 0.037 ;
     RECT  19.998 0.012 20.052 0.037 ;
     RECT  20.07 0.012 20.124 0.037 ;
     RECT  20.142 0.012 20.196 0.037 ;
     RECT  20.214 0.012 20.268 0.037 ;
     RECT  20.286 0.012 20.34 0.037 ;
     RECT  20.358 0.012 20.412 0.037 ;
     RECT  20.43 0.012 20.484 0.037 ;
     RECT  20.502 0.012 20.556 0.037 ;
     RECT  20.574 0.012 20.628 0.037 ;
     RECT  20.646 0.012 20.7 0.037 ;
     RECT  20.718 0.012 20.772 0.037 ;
     RECT  20.79 0.012 20.844 0.037 ;
     RECT  20.862 0.012 20.916 0.037 ;
     RECT  20.934 0.012 20.988 0.037 ;
     RECT  21.006 0.012 21.06 0.037 ;
     RECT  21.078 0.012 21.132 0.037 ;
     RECT  21.15 0.012 21.204 0.037 ;
     RECT  21.222 0.012 21.276 0.037 ;
     RECT  21.294 0.012 21.348 0.037 ;
     RECT  21.366 0.012 21.42 0.037 ;
     RECT  21.438 0.012 21.492 0.037 ;
     RECT  21.51 0.012 21.564 0.037 ;
     RECT  21.582 0.012 21.636 0.037 ;
     RECT  21.654 0.012 21.708 0.037 ;
     RECT  21.726 0.012 21.78 0.037 ;
     RECT  17.244 0.037 21.798 0.175 ;
     RECT  28.836 0.091 28.854 0.269 ;
     RECT  25.236 0.379 25.254 0.427 ;
     RECT  25.236 0.427 25.758 0.475 ;
     RECT  25.236 0.475 26.118 0.523 ;
     RECT  11.232 0.091 12.078 0.841 ;
     RECT  13.86 0.139 14.598 0.913 ;
     RECT  9.576 0.091 9.594 1.099 ;
     RECT  24.768 0.523 26.118 1.099 ;
     RECT  15.876 0.811 15.894 1.147 ;
     RECT  13.86 0.913 14.67 1.417 ;
     RECT  9.468 1.099 9.594 1.723 ;
     RECT  9.432 1.723 9.594 1.771 ;
     RECT  24.768 1.099 26.694 1.915 ;
     RECT  27.648 0.523 27.666 1.915 ;
     RECT  4.68 0.103 7.398 2.143 ;
     RECT  11.232 0.841 12.582 2.143 ;
     RECT  13.86 1.417 14.814 2.143 ;
     RECT  24.768 1.915 27.666 2.143 ;
     RECT  29.415 2.143 29.505 2.203 ;
     RECT  9.432 1.771 9.666 2.251 ;
     RECT  10.515 2.143 14.814 2.251 ;
     RECT  24.015 2.143 27.666 2.251 ;
     RECT  29.016 2.203 29.505 2.251 ;
     RECT  15.876 1.147 16.29 2.299 ;
     RECT  2.415 2.143 2.505 2.413 ;
     RECT  4.68 2.143 7.905 2.413 ;
     RECT  24.015 2.251 29.505 2.413 ;
     RECT  9.432 2.251 14.814 2.461 ;
     RECT  15.768 2.299 16.29 2.461 ;
     RECT  17.1 0.175 21.798 2.461 ;
     RECT  9.432 2.461 21.798 2.641 ;
     RECT  2.415 2.413 2.697 2.731 ;
     RECT  3.636 2.641 3.654 2.731 ;
     RECT  9.216 2.641 21.798 2.803 ;
     RECT  2.415 2.731 3.654 2.911 ;
     RECT  4.68 2.413 8.097 2.911 ;
     RECT  2.415 2.911 8.097 3.181 ;
     RECT  9.216 2.803 22.158 3.181 ;
     RECT  23.148 2.263 23.166 3.451 ;
     RECT  23.148 3.451 23.274 3.613 ;
     RECT  24.015 2.413 29.697 3.613 ;
     RECT  23.148 3.613 29.697 4.955 ;
     RECT  23.148 4.955 27.594 5.971 ;
     RECT  28.332 4.955 29.697 5.971 ;
     RECT  2.415 3.181 22.158 6.853 ;
     RECT  2.415 6.853 22.23 7.771 ;
     RECT  23.148 5.971 29.697 7.771 ;
     RECT  2.415 7.771 29.697 8.573 ;
     RECT  2.415 8.573 22.338 10.165 ;
     RECT  23.148 8.573 29.697 10.165 ;
     RECT  2.415 10.165 29.697 10.291 ;
     RECT  2.415 10.291 29.862 10.859 ;
     RECT  2.415 10.859 29.754 11.003 ;
     RECT  2.415 11.003 29.697 12.757 ;
     RECT  2.415 12.757 29.934 14.099 ;
     RECT  2.415 14.099 29.79 14.135 ;
     RECT  2.415 14.135 29.697 14.513 ;
     RECT  2.415 14.513 22.194 15.295 ;
     RECT  23.148 14.513 29.697 15.295 ;
     RECT  2.415 15.295 29.697 15.457 ;
     RECT  2.415 15.457 29.862 16.555 ;
     RECT  2.376 16.555 29.862 16.799 ;
     RECT  2.376 16.799 29.826 16.907 ;
     RECT  2.376 16.907 29.754 16.943 ;
     RECT  2.376 16.943 29.697 17.995 ;
     RECT  2.376 17.995 29.862 18.185 ;
     RECT  2.415 18.185 29.862 18.535 ;
     RECT  2.415 18.535 30.114 18.959 ;
     RECT  2.415 18.959 29.79 19.229 ;
     RECT  2.415 19.229 29.697 20.857 ;
     RECT  2.415 20.857 29.826 21.659 ;
     RECT  2.415 21.659 29.697 22.891 ;
     RECT  2.415 22.891 29.79 23.693 ;
     RECT  2.415 23.693 29.697 23.971 ;
     RECT  2.376 23.971 29.697 24.935 ;
     RECT  2.415 24.935 29.697 25.051 ;
     RECT  2.415 25.051 29.79 25.583 ;
     RECT  2.415 25.583 29.697 27.365 ;
     RECT  2.415 27.365 22.878 27.599 ;
     RECT  2.415 27.599 22.734 27.635 ;
     RECT  2.415 27.635 22.518 28.219 ;
     RECT  2.376 28.219 22.518 28.381 ;
     RECT  2.376 28.381 22.734 28.409 ;
     RECT  2.415 28.409 22.734 28.411 ;
     RECT  23.652 27.365 29.697 28.411 ;
     RECT  2.415 28.411 29.697 29.489 ;
     RECT  23.292 29.489 29.697 29.645 ;
     RECT  2.415 29.489 22.518 29.731 ;
     RECT  2.376 29.731 22.518 29.789 ;
     RECT  23.436 29.645 29.697 30.109 ;
     RECT  23.436 30.109 29.754 30.209 ;
     RECT  23.616 30.209 29.754 30.569 ;
     RECT  2.415 29.789 22.518 30.811 ;
     RECT  2.415 30.811 22.77 31.261 ;
     RECT  23.616 30.569 29.697 31.261 ;
     RECT  2.415 31.261 29.697 31.531 ;
     RECT  2.304 31.531 29.697 31.891 ;
     RECT  2.304 31.891 29.754 32.459 ;
     RECT  2.304 32.459 29.697 32.495 ;
     RECT  2.415 32.495 29.697 34.219 ;
     RECT  2.376 34.219 29.697 35.159 ;
     RECT  2.415 35.159 29.697 36.211 ;
     RECT  2.415 36.211 29.754 36.779 ;
     RECT  2.415 36.779 29.697 37.741 ;
     RECT  2.415 37.741 30.042 38.669 ;
     RECT  30.78 38.209 30.798 38.779 ;
     RECT  2.415 38.669 29.898 38.939 ;
     RECT  2.415 38.939 22.482 39.091 ;
     RECT  2.376 39.091 22.482 39.119 ;
     RECT  32.292 38.971 32.31 39.149 ;
     RECT  23.292 38.939 29.898 39.209 ;
     RECT  2.376 39.119 22.158 39.245 ;
     RECT  30.78 38.779 30.87 39.341 ;
     RECT  23.868 39.209 29.898 39.533 ;
     RECT  30.744 39.595 30.762 39.632 ;
     RECT  2.415 39.245 22.158 40.019 ;
     RECT  23.868 39.533 29.697 40.055 ;
     RECT  2.415 40.019 21.597 40.091 ;
     RECT  2.415 40.091 9.342 40.325 ;
     RECT  2.415 40.325 8.154 40.397 ;
     RECT  9.252 40.325 9.342 40.595 ;
     RECT  10.476 40.091 21.597 40.595 ;
     RECT  9.252 40.595 9.27 40.667 ;
     RECT  10.476 40.595 12.294 40.739 ;
     RECT  2.415 40.397 8.097 40.787 ;
     RECT  13.176 40.595 21.597 40.787 ;
     RECT  24.015 40.055 29.697 40.787 ;
     RECT  3.276 40.787 7.905 40.829 ;
     RECT  13.176 40.787 21.405 40.829 ;
     RECT  24.948 40.787 29.505 40.829 ;
     RECT  3.276 40.829 5.994 40.865 ;
     RECT  10.476 40.739 11.682 40.865 ;
     RECT  13.176 40.829 19.566 40.865 ;
     RECT  24.948 40.829 28.134 40.865 ;
     RECT  24.948 40.865 27.738 40.877 ;
     RECT  29.232 40.829 29.505 40.901 ;
     RECT  3.348 40.865 5.994 40.973 ;
     RECT  13.215 40.865 19.494 40.973 ;
     RECT  7.164 40.829 7.905 41.009 ;
     RECT  10.515 40.865 11.286 41.009 ;
     RECT  18.036 40.973 19.494 41.009 ;
     RECT  20.304 40.829 21.405 41.009 ;
     RECT  3.348 40.973 5.67 41.021 ;
     RECT  20.304 41.009 20.322 41.021 ;
     RECT  2.415 40.787 2.505 41.057 ;
     RECT  7.815 41.009 7.905 41.057 ;
     RECT  10.515 41.009 11.142 41.057 ;
     RECT  13.215 40.973 17.19 41.057 ;
     RECT  18.036 41.009 19.35 41.057 ;
     RECT  21.204 41.009 21.405 41.057 ;
     RECT  24.015 40.787 24.105 41.057 ;
     RECT  29.415 40.901 29.505 41.057 ;
     RECT  24.948 40.877 27.558 41.135 ;
     RECT  19.332 41.057 19.35 41.165 ;
     RECT  13.356 41.057 17.19 41.213 ;
     RECT  18.036 41.057 18.558 41.213 ;
     RECT  3.384 41.021 5.67 41.261 ;
     RECT  13.356 41.213 15.138 41.597 ;
     RECT  16.308 41.213 17.19 41.597 ;
     RECT  3.384 41.261 5.526 42.173 ;
     RECT  13.392 41.597 14.382 42.173 ;
     RECT  15.12 41.597 15.138 42.173 ;
     RECT  17.1 41.597 17.118 42.173 ;
     RECT  18.036 41.213 18.054 42.173 ;
     RECT  4.824 42.173 5.526 42.221 ;
     RECT  13.536 42.173 14.382 42.797 ;
     RECT  3.384 42.173 3.978 43.037 ;
     RECT  10.656 41.057 11.142 43.069 ;
     RECT  3.384 43.037 3.87 43.085 ;
     RECT  4.824 42.221 4.842 43.085 ;
     RECT  13.86 42.797 14.382 43.085 ;
     RECT  18.792 43.003 18.81 43.133 ;
     RECT  21.204 41.057 21.222 43.133 ;
     RECT  10.62 43.069 11.142 43.141 ;
     RECT  10.548 43.141 11.142 43.163 ;
     RECT  10.566 43.163 10.62 43.169 ;
     RECT  10.638 43.163 10.692 43.169 ;
     RECT  10.71 43.163 10.764 43.169 ;
     RECT  10.782 43.163 10.836 43.169 ;
     RECT  10.854 43.163 10.908 43.169 ;
     RECT  10.926 43.163 10.98 43.169 ;
     RECT  10.998 43.163 11.052 43.169 ;
     RECT  11.07 43.163 11.142 43.169 ;
     RECT  10.566 43.169 10.62 43.181 ;
     RECT  10.638 43.169 10.692 43.181 ;
     RECT  10.71 43.169 10.764 43.181 ;
     RECT  10.782 43.169 10.836 43.181 ;
     RECT  10.854 43.169 10.908 43.181 ;
     RECT  10.926 43.169 10.98 43.181 ;
     RECT  10.998 43.169 11.052 43.181 ;
     RECT  24.948 41.135 27.198 43.163 ;
     RECT  24.966 43.163 25.02 43.181 ;
     RECT  25.038 43.163 25.092 43.181 ;
     RECT  25.11 43.163 25.164 43.181 ;
     RECT  25.182 43.163 25.236 43.181 ;
     RECT  25.254 43.163 25.308 43.181 ;
     RECT  25.326 43.163 25.38 43.181 ;
     RECT  25.398 43.163 25.452 43.181 ;
     RECT  25.47 43.163 25.524 43.181 ;
     RECT  25.542 43.163 25.596 43.181 ;
     RECT  25.614 43.163 25.668 43.181 ;
     RECT  25.686 43.163 25.74 43.181 ;
     RECT  25.758 43.163 25.812 43.181 ;
     RECT  25.83 43.163 25.884 43.181 ;
     RECT  25.902 43.163 25.956 43.181 ;
     RECT  25.974 43.163 26.028 43.181 ;
     RECT  26.046 43.163 26.1 43.181 ;
     RECT  26.118 43.163 26.172 43.181 ;
     RECT  26.19 43.163 26.244 43.181 ;
     RECT  26.262 43.163 26.316 43.181 ;
     RECT  26.334 43.163 26.388 43.181 ;
     RECT  26.406 43.163 26.46 43.181 ;
     RECT  26.478 43.163 26.532 43.181 ;
     RECT  26.55 43.163 26.604 43.181 ;
     RECT  26.622 43.163 26.676 43.181 ;
     RECT  26.694 43.163 26.748 43.181 ;
     RECT  26.766 43.163 26.82 43.181 ;
     RECT  26.838 43.163 26.892 43.181 ;
     RECT  26.91 43.163 26.964 43.181 ;
     RECT  26.982 43.163 27.036 43.181 ;
     RECT  27.054 43.163 27.108 43.181 ;
     RECT  27.126 43.163 27.18 43.181 ;
    LAYER M4 ;
     RECT  2.365 16.56 2.408 16.584 ;
     RECT  2.365 17.616 2.408 17.64 ;
     RECT  2.365 24.096 2.408 24.12 ;
     RECT  2.365 29.76 2.408 29.784 ;
     RECT  2.252 32.448 2.408 32.472 ;
     RECT  2.293 34.224 2.408 34.248 ;
     RECT  2.365 39.216 2.408 39.24 ;
     RECT  2.408 2.148 2.512 41.052 ;
     RECT  2.512 2.418 2.704 41.016 ;
     RECT  2.704 12.528 2.981 15.48 ;
     RECT  2.704 34.224 3.251 36.504 ;
     RECT  2.704 22.272 3.269 22.296 ;
     RECT  2.704 37.872 3.449 39.768 ;
     RECT  3.373 43.056 3.481 43.08 ;
     RECT  2.704 28.128 3.485 28.248 ;
     RECT  2.704 23.856 3.557 24.12 ;
     RECT  3.481 42.144 3.564 43.08 ;
     RECT  2.704 40.8 3.661 41.016 ;
     RECT  2.981 12.528 3.676 14.664 ;
     RECT  3.251 34.224 3.737 35.928 ;
     RECT  2.704 16.56 3.805 16.584 ;
     RECT  2.704 17.616 3.805 17.64 ;
     RECT  2.704 26.352 3.805 26.808 ;
     RECT  3.449 38.784 3.809 39.768 ;
     RECT  2.704 29.76 3.841 29.784 ;
     RECT  2.704 30.96 3.841 31.176 ;
     RECT  3.676 12.528 3.877 13.128 ;
     RECT  2.704 19.536 3.949 19.56 ;
     RECT  3.805 15.84 3.971 16.584 ;
     RECT  3.661 40.8 4.057 41.064 ;
     RECT  3.564 42.096 4.057 43.08 ;
     RECT  3.676 14.208 4.067 14.664 ;
     RECT  3.557 23.952 4.237 24.12 ;
     RECT  3.877 12.384 4.261 13.128 ;
     RECT  3.949 19.536 4.261 19.656 ;
     RECT  4.021 21.12 4.261 21.144 ;
     RECT  3.841 29.76 4.261 31.176 ;
     RECT  4.057 40.8 4.277 43.08 ;
     RECT  3.805 26.352 4.309 27.336 ;
     RECT  4.067 14.64 4.345 14.664 ;
     RECT  3.805 17.616 4.517 18.024 ;
     RECT  4.261 19.536 4.517 21.144 ;
     RECT  3.809 39.744 4.645 39.768 ;
     RECT  4.277 40.8 4.645 41.64 ;
     RECT  3.971 16.416 4.789 16.584 ;
     RECT  4.517 17.616 4.789 21.144 ;
     RECT  4.277 43.056 4.853 43.08 ;
     RECT  4.453 37.44 4.885 37.464 ;
     RECT  4.261 11.952 4.933 13.128 ;
     RECT  3.737 34.752 4.933 35.928 ;
     RECT  4.885 37.44 4.933 38.184 ;
     RECT  4.309 26.112 5.029 27.336 ;
     RECT  4.933 11.952 5.108 13.608 ;
     RECT  4.345 14.64 5.108 15.384 ;
     RECT  4.789 16.416 5.108 21.144 ;
     RECT  4.669 22.464 5.108 22.488 ;
     RECT  4.237 23.952 5.108 24.504 ;
     RECT  5.029 25.728 5.108 27.336 ;
     RECT  4.261 29.184 5.108 31.176 ;
     RECT  4.381 32.352 5.108 32.376 ;
     RECT  4.933 34.752 5.108 38.184 ;
     RECT  4.645 39.744 5.108 41.64 ;
     RECT  5.108 2.148 5.212 41.64 ;
     RECT  5.212 2.418 5.404 41.64 ;
     RECT  5.404 34.224 5.497 41.64 ;
     RECT  5.497 34.224 5.555 42.216 ;
     RECT  5.555 34.224 5.603 37.608 ;
     RECT  5.404 12.24 5.651 17.64 ;
     RECT  5.555 38.592 5.651 42.216 ;
     RECT  5.651 38.592 5.681 41.256 ;
     RECT  5.404 32.4 5.717 33.048 ;
     RECT  5.603 36.528 5.725 37.608 ;
     RECT  5.651 12.24 5.795 15.432 ;
     RECT  5.404 18.672 5.843 20.136 ;
     RECT  5.795 12.24 5.891 13.512 ;
     RECT  5.795 14.784 5.939 15.432 ;
     RECT  5.725 36.528 5.939 37.464 ;
     RECT  5.404 22.464 6.005 22.728 ;
     RECT  5.651 16.56 6.113 17.64 ;
     RECT  5.404 23.952 6.257 25.752 ;
     RECT  5.939 14.784 6.293 15.048 ;
     RECT  5.843 18.672 6.329 18.984 ;
     RECT  6.257 23.952 6.329 24.504 ;
     RECT  6.113 16.56 6.365 17.112 ;
     RECT  5.404 21.216 6.397 21.24 ;
     RECT  5.603 34.224 6.419 35.448 ;
     RECT  6.397 21.216 6.509 21.384 ;
     RECT  5.717 33.024 6.541 33.048 ;
     RECT  6.419 34.224 6.541 34.824 ;
     RECT  6.257 25.728 6.577 25.752 ;
     RECT  6.329 24.48 6.581 24.504 ;
     RECT  6.005 22.704 6.617 22.728 ;
     RECT  5.891 13.008 6.653 13.512 ;
     RECT  6.577 25.728 6.761 25.992 ;
     RECT  5.404 28.176 6.761 28.2 ;
     RECT  5.939 37.44 6.805 37.464 ;
     RECT  5.681 38.592 6.805 40.968 ;
     RECT  6.329 18.672 6.833 18.696 ;
     RECT  5.404 29.232 6.833 29.352 ;
     RECT  5.404 30.768 6.973 31.176 ;
     RECT  6.805 37.44 7.441 40.968 ;
     RECT  7.441 37.104 7.469 40.968 ;
     RECT  6.509 21.36 7.477 21.384 ;
     RECT  6.365 16.8 7.525 17.112 ;
     RECT  7.525 16.416 7.621 17.112 ;
     RECT  7.585 22.752 7.629 22.776 ;
     RECT  7.621 16.272 7.657 17.112 ;
     RECT  6.761 25.968 7.657 25.992 ;
     RECT  7.657 16.08 7.669 17.112 ;
     RECT  6.973 30.576 7.669 31.176 ;
     RECT  7.669 24.624 7.729 24.648 ;
     RECT  7.657 25.968 7.729 26.664 ;
     RECT  6.833 29.328 7.801 29.352 ;
     RECT  6.829 13.536 7.808 13.56 ;
     RECT  6.293 14.784 7.808 14.808 ;
     RECT  7.669 16.08 7.808 17.736 ;
     RECT  5.843 20.112 7.808 20.136 ;
     RECT  7.477 21.36 7.808 21.576 ;
     RECT  7.629 22.752 7.808 23.592 ;
     RECT  7.729 24.624 7.808 26.664 ;
     RECT  7.801 28.992 7.808 29.352 ;
     RECT  7.669 30.576 7.808 31.512 ;
     RECT  6.541 33.024 7.808 34.824 ;
     RECT  6.757 35.952 7.808 35.976 ;
     RECT  7.469 37.056 7.808 40.968 ;
     RECT  7.808 2.148 7.912 41.052 ;
     RECT  7.912 2.418 8.104 40.782 ;
     RECT  8.104 40.032 8.237 40.152 ;
     RECT  8.104 25.296 8.243 29.688 ;
     RECT  8.104 19.968 8.291 20.568 ;
     RECT  8.104 31.488 8.291 33.048 ;
     RECT  8.291 32.976 8.309 33.048 ;
     RECT  8.291 31.488 8.381 31.944 ;
     RECT  8.381 31.92 8.483 31.944 ;
     RECT  8.243 25.296 8.489 28.296 ;
     RECT  8.104 15.84 8.525 16.824 ;
     RECT  8.489 25.296 8.533 27.384 ;
     RECT  8.309 33.024 8.597 33.048 ;
     RECT  8.104 37.872 8.597 38.808 ;
     RECT  8.533 25.296 8.62 27.24 ;
     RECT  8.104 34.128 8.723 34.776 ;
     RECT  8.104 35.952 8.723 35.976 ;
     RECT  8.243 29.328 8.921 29.688 ;
     RECT  8.104 22.752 9.029 23.592 ;
     RECT  8.62 25.296 9.029 26.664 ;
     RECT  8.237 40.032 9.097 40.056 ;
     RECT  9.029 26.256 9.173 26.664 ;
     RECT  8.525 16.08 9.212 16.824 ;
     RECT  9.205 17.904 9.212 17.928 ;
     RECT  8.597 37.872 9.241 38.184 ;
     RECT  9.164 36.24 9.251 36.264 ;
     RECT  9.029 22.752 9.281 22.776 ;
     RECT  9.212 16.08 9.299 17.928 ;
     RECT  9.241 37.248 9.349 38.184 ;
     RECT  9.349 1.728 9.445 1.752 ;
     RECT  9.445 1.728 9.457 1.8 ;
     RECT  9.349 37.104 9.461 38.184 ;
     RECT  8.291 20.544 9.529 20.568 ;
     RECT  9.457 1.104 9.596 1.8 ;
     RECT  9.596 1.104 9.677 2.28 ;
     RECT  9.673 13.104 9.817 13.128 ;
     RECT  9.677 1.104 9.971 1.128 ;
     RECT  9.097 39.888 10.033 40.056 ;
     RECT  9.461 37.2 10.105 38.184 ;
     RECT  10.033 39.216 10.105 40.056 ;
     RECT  9.173 26.256 10.213 26.28 ;
     RECT  9.997 24.96 10.285 24.984 ;
     RECT  10.213 26.256 10.324 26.712 ;
     RECT  10.285 24.48 10.501 24.984 ;
     RECT  9.677 2.148 10.508 2.28 ;
     RECT  9.817 13.104 10.508 13.608 ;
     RECT  9.673 14.832 10.508 14.856 ;
     RECT  9.299 16.08 10.508 16.104 ;
     RECT  9.299 17.616 10.508 17.928 ;
     RECT  9.596 19.2 10.508 19.224 ;
     RECT  9.529 20.304 10.508 21.528 ;
     RECT  10.501 23.904 10.508 24.984 ;
     RECT  10.324 26.256 10.508 26.76 ;
     RECT  8.921 29.328 10.508 29.352 ;
     RECT  9.817 32.832 10.508 32.856 ;
     RECT  8.723 34.128 10.508 34.152 ;
     RECT  9.205 35.184 10.508 35.208 ;
     RECT  10.105 37.2 10.508 40.056 ;
     RECT  10.508 2.148 10.612 41.052 ;
     RECT  10.612 2.418 10.804 40.872 ;
     RECT  10.804 23.856 10.829 24.984 ;
     RECT  10.804 27.888 10.829 29.352 ;
     RECT  10.804 37.584 10.973 40.872 ;
     RECT  10.973 37.584 11.045 40.056 ;
     RECT  10.804 17.568 11.075 20.664 ;
     RECT  10.804 13.584 11.153 13.608 ;
     RECT  9.565 0.096 11.261 0.12 ;
     RECT  11.075 19.344 11.267 20.664 ;
     RECT  10.804 30.816 11.297 31.32 ;
     RECT  10.829 27.888 11.363 29.112 ;
     RECT  10.804 16.08 11.405 16.104 ;
     RECT  11.267 19.968 11.585 20.664 ;
     RECT  10.829 23.856 11.837 23.928 ;
     RECT  11.833 14.688 12.017 14.712 ;
     RECT  11.869 16.224 12.017 16.248 ;
     RECT  11.363 28.512 12.085 29.112 ;
     RECT  10.804 21.648 12.131 21.768 ;
     RECT  10.804 35.184 12.157 35.208 ;
     RECT  12.085 22.8 12.197 22.824 ;
     RECT  12.157 34.8 12.197 35.208 ;
     RECT  10.804 33.408 12.229 33.432 ;
     RECT  12.197 34.8 12.229 34.824 ;
     RECT  12.229 32.448 12.241 34.824 ;
     RECT  11.075 17.568 12.301 17.928 ;
     RECT  11.297 30.816 12.337 30.84 ;
     RECT  10.804 10.416 12.409 10.44 ;
     RECT  12.301 17.568 12.517 18.168 ;
     RECT  12.085 28.512 12.589 29.208 ;
     RECT  11.585 20.64 12.625 20.664 ;
     RECT  12.409 10.416 12.661 10.968 ;
     RECT  11.869 12.192 12.661 12.216 ;
     RECT  11.045 38.16 12.709 40.056 ;
     RECT  12.517 17.088 12.985 18.168 ;
     RECT  12.625 20.256 12.997 20.664 ;
     RECT  11.941 6.816 13.093 6.84 ;
     RECT  12.661 10.416 13.093 12.216 ;
     RECT  12.985 17.088 13.093 18.216 ;
     RECT  12.985 4.656 13.208 4.68 ;
     RECT  13.093 6.672 13.208 6.84 ;
     RECT  12.445 8.448 13.208 8.472 ;
     RECT  13.093 10.416 13.208 13.704 ;
     RECT  12.877 14.832 13.208 14.856 ;
     RECT  13.093 16.272 13.208 18.216 ;
     RECT  12.997 19.488 13.208 20.664 ;
     RECT  12.131 21.744 13.208 21.768 ;
     RECT  11.837 23.856 13.208 23.88 ;
     RECT  12.661 25.104 13.208 25.128 ;
     RECT  12.769 27.168 13.208 27.192 ;
     RECT  12.589 28.512 13.208 29.352 ;
     RECT  12.337 30.336 13.208 30.84 ;
     RECT  12.241 32.448 13.208 34.2 ;
     RECT  12.709 37.44 13.208 40.056 ;
     RECT  13.208 2.148 13.285 41.052 ;
     RECT  13.285 2.148 13.312 41.592 ;
     RECT  13.312 2.418 13.381 41.592 ;
     RECT  13.381 2.418 13.477 42.168 ;
     RECT  13.477 2.418 13.504 42.792 ;
     RECT  13.504 34.176 13.637 34.92 ;
     RECT  13.504 3.312 13.715 4.728 ;
     RECT  13.504 19.872 13.781 22.056 ;
     RECT  13.504 38.64 13.849 42.792 ;
     RECT  13.504 8.016 14.069 11.688 ;
     RECT  13.504 6.672 14.141 6.888 ;
     RECT  13.504 30.336 14.213 32.184 ;
     RECT  13.781 20.64 14.329 22.056 ;
     RECT  13.504 26.304 14.393 27.336 ;
     RECT  13.504 28.944 14.393 29.352 ;
     RECT  13.849 38.64 14.393 43.08 ;
     RECT  14.393 26.304 14.501 26.808 ;
     RECT  14.393 38.64 14.537 42.168 ;
     RECT  13.504 16.896 14.605 18.168 ;
     RECT  14.069 8.448 14.609 11.688 ;
     RECT  14.609 10.272 14.627 11.688 ;
     RECT  14.609 8.736 14.645 8.76 ;
     RECT  14.627 10.896 14.645 11.688 ;
     RECT  14.501 26.64 14.681 26.808 ;
     RECT  13.637 34.896 14.741 34.92 ;
     RECT  14.741 33.984 14.749 34.92 ;
     RECT  14.537 38.64 14.749 39.24 ;
     RECT  14.213 30.768 14.773 32.184 ;
     RECT  14.749 33.696 14.773 34.92 ;
     RECT  14.645 10.944 14.789 11.688 ;
     RECT  14.773 30.768 14.819 34.92 ;
     RECT  14.819 32.928 14.825 34.92 ;
     RECT  14.825 32.928 14.86 33.72 ;
     RECT  14.329 20.64 14.861 21.096 ;
     RECT  13.715 3.84 14.893 4.728 ;
     RECT  13.504 13.632 14.924 13.656 ;
     RECT  13.504 14.64 14.924 14.904 ;
     RECT  14.924 13.632 14.965 14.904 ;
     RECT  14.141 6.672 15.109 6.84 ;
     RECT  14.965 13.632 15.145 15.432 ;
     RECT  14.605 16.896 15.145 18.6 ;
     RECT  15.145 13.632 15.361 18.744 ;
     RECT  13.504 24.48 15.5 24.504 ;
     RECT  14.893 3.552 15.613 4.728 ;
     RECT  15.361 13.632 15.613 19.368 ;
     RECT  15.613 13.104 15.729 19.368 ;
     RECT  14.393 29.328 15.757 29.352 ;
     RECT  15.729 12.816 15.781 19.368 ;
     RECT  15.757 29.328 15.829 29.544 ;
     RECT  14.749 38.352 15.865 39.24 ;
     RECT  14.537 40.272 15.865 42.168 ;
     RECT  14.681 26.784 15.901 26.808 ;
     RECT  14.86 33.696 15.901 33.72 ;
     RECT  15.613 2.88 15.908 4.728 ;
     RECT  15.109 6.576 15.908 6.84 ;
     RECT  14.789 11.424 15.908 11.688 ;
     RECT  15.781 12.816 15.908 19.656 ;
     RECT  14.861 20.64 15.908 21 ;
     RECT  15.469 22.608 15.908 22.632 ;
     RECT  15.5 23.712 15.908 24.504 ;
     RECT  15.781 25.68 15.908 25.704 ;
     RECT  15.901 26.784 15.908 26.904 ;
     RECT  15.829 29.232 15.908 29.544 ;
     RECT  14.819 30.768 15.908 31.752 ;
     RECT  15.901 33.552 15.908 33.72 ;
     RECT  14.825 34.896 15.908 34.92 ;
     RECT  15.865 38.352 15.908 42.168 ;
     RECT  15.908 2.148 15.973 42.168 ;
     RECT  15.973 2.148 16.012 43.032 ;
     RECT  16.012 2.418 16.204 43.032 ;
     RECT  16.204 18.72 16.229 18.888 ;
     RECT  16.204 3.84 16.355 6.888 ;
     RECT  16.204 33.024 16.355 34.824 ;
     RECT  16.204 36.24 16.355 43.032 ;
     RECT  16.355 3.84 16.445 5.112 ;
     RECT  16.355 36.24 16.451 42.984 ;
     RECT  16.355 6.48 16.481 6.888 ;
     RECT  16.229 18.768 16.517 18.888 ;
     RECT  16.204 25.824 16.547 29.688 ;
     RECT  16.451 36.24 16.547 42.936 ;
     RECT  16.481 6.48 16.553 6.84 ;
     RECT  16.204 10.656 16.589 15.864 ;
     RECT  16.547 36.24 16.625 42.168 ;
     RECT  16.204 22.176 16.769 22.632 ;
     RECT  16.445 3.84 16.805 4.584 ;
     RECT  16.625 36.24 16.805 37.032 ;
     RECT  16.553 6.72 16.835 6.84 ;
     RECT  16.547 26.448 16.841 29.688 ;
     RECT  16.589 10.656 16.949 15.336 ;
     RECT  16.841 26.544 16.979 29.688 ;
     RECT  16.949 10.656 17.021 13.032 ;
     RECT  16.625 38.16 17.021 42.168 ;
     RECT  16.517 18.768 17.129 18.792 ;
     RECT  16.204 2.736 17.197 2.856 ;
     RECT  16.805 3.84 17.197 3.864 ;
     RECT  16.355 34.8 17.201 34.824 ;
     RECT  17.021 38.208 17.201 42.168 ;
     RECT  16.204 17.472 17.269 17.64 ;
     RECT  16.949 14.16 17.309 15.336 ;
     RECT  16.204 8.16 17.341 8.712 ;
     RECT  17.021 10.896 17.345 13.032 ;
     RECT  16.204 24.48 17.377 24.552 ;
     RECT  17.269 17.088 17.381 17.64 ;
     RECT  16.355 33.024 17.413 33.192 ;
     RECT  17.381 17.472 17.417 17.64 ;
     RECT  17.413 33.024 17.449 33.384 ;
     RECT  17.417 17.616 17.521 17.64 ;
     RECT  16.204 19.968 17.596 21.096 ;
     RECT  16.979 29.664 17.597 29.688 ;
     RECT  17.449 33.024 17.737 33.576 ;
     RECT  17.737 33.024 17.909 33.624 ;
     RECT  17.309 15.312 17.917 15.336 ;
     RECT  17.377 24.384 17.917 24.552 ;
     RECT  16.769 22.176 17.941 22.488 ;
     RECT  16.204 30.816 17.941 31.752 ;
     RECT  17.909 33.024 17.941 34.776 ;
     RECT  17.941 22.08 17.989 22.488 ;
     RECT  16.835 6.72 18.025 6.744 ;
     RECT  17.197 2.736 18.061 3.864 ;
     RECT  17.201 42.144 18.065 42.168 ;
     RECT  17.201 38.208 18.085 41.016 ;
     RECT  18.061 2.736 18.133 4.68 ;
     RECT  18.025 6.288 18.177 6.744 ;
     RECT  17.345 11.52 18.197 13.032 ;
     RECT  17.309 14.16 18.197 14.184 ;
     RECT  17.941 30.816 18.277 34.776 ;
     RECT  16.805 36.24 18.277 36.936 ;
     RECT  18.085 38.16 18.352 41.016 ;
     RECT  18.277 36.24 18.373 37.176 ;
     RECT  18.352 38.16 18.373 41.064 ;
     RECT  18.277 30.24 18.385 34.776 ;
     RECT  18.373 36.24 18.385 41.064 ;
     RECT  18.385 30.24 18.529 41.064 ;
     RECT  18.133 2.256 18.608 4.68 ;
     RECT  18.177 6.288 18.608 7.128 ;
     RECT  17.341 8.16 18.608 9.144 ;
     RECT  18.241 10.416 18.608 10.44 ;
     RECT  18.197 11.52 18.608 14.184 ;
     RECT  17.917 15.312 18.608 15.672 ;
     RECT  17.521 17.616 18.608 17.928 ;
     RECT  17.596 19.968 18.608 21 ;
     RECT  17.989 22.08 18.608 22.824 ;
     RECT  17.917 23.952 18.608 24.552 ;
     RECT  16.979 26.544 18.608 27.96 ;
     RECT  18.236 28.944 18.608 28.968 ;
     RECT  18.529 30.24 18.608 41.208 ;
     RECT  18.608 2.148 18.707 41.208 ;
     RECT  18.707 2.148 18.712 41.16 ;
     RECT  18.421 42.96 18.781 43.032 ;
     RECT  18.712 2.418 18.904 41.16 ;
     RECT  18.904 35.424 18.965 35.448 ;
     RECT  18.904 9.264 19.037 9.288 ;
     RECT  18.781 42.96 19.043 43.128 ;
     RECT  15.865 0.816 19.073 0.84 ;
     RECT  18.904 14.496 19.101 15.336 ;
     RECT  18.904 30.48 19.181 31.752 ;
     RECT  18.904 4.128 19.253 5.112 ;
     RECT  18.904 6.768 19.289 7.128 ;
     RECT  18.904 38.688 19.361 41.16 ;
     RECT  18.904 36.912 19.433 37.608 ;
     RECT  19.253 4.512 19.523 5.112 ;
     RECT  18.904 20.16 19.541 20.664 ;
     RECT  18.904 27.936 19.541 27.96 ;
     RECT  19.541 20.256 19.564 20.664 ;
     RECT  18.904 25.632 19.577 26.856 ;
     RECT  18.904 22.08 19.649 22.824 ;
     RECT  18.904 10.416 19.757 10.44 ;
     RECT  19.577 25.632 19.757 26.808 ;
     RECT  19.361 38.688 19.829 41.016 ;
     RECT  18.904 12.864 19.897 13.128 ;
     RECT  19.564 20.592 19.897 20.664 ;
     RECT  19.649 22.08 19.897 22.536 ;
     RECT  19.181 30.48 19.909 30.504 ;
     RECT  19.909 30.192 19.955 30.504 ;
     RECT  19.868 32.976 19.955 33 ;
     RECT  18.904 2.496 20.009 3.096 ;
     RECT  19.829 40.608 20.009 41.016 ;
     RECT  19.957 27.792 20.044 27.816 ;
     RECT  20.009 2.496 20.117 3.048 ;
     RECT  18.904 24.144 20.149 24.168 ;
     RECT  19.829 38.688 20.153 39.096 ;
     RECT  19.101 14.496 20.189 14.52 ;
     RECT  19.897 11.952 20.221 13.128 ;
     RECT  19.289 6.768 20.261 6.888 ;
     RECT  20.009 40.848 20.333 41.016 ;
     RECT  18.904 17.616 20.365 18.456 ;
     RECT  20.149 23.904 20.365 24.168 ;
     RECT  20.365 17.376 20.437 18.456 ;
     RECT  19.433 37.44 20.473 37.608 ;
     RECT  19.181 31.584 20.485 31.752 ;
     RECT  20.077 10.704 20.509 10.728 ;
     RECT  20.437 17.328 20.509 18.456 ;
     RECT  20.365 23.712 20.509 24.168 ;
     RECT  20.485 31.584 20.545 31.896 ;
     RECT  20.509 17.328 20.581 18.744 ;
     RECT  20.473 37.44 20.581 37.656 ;
     RECT  20.153 38.688 20.581 39 ;
     RECT  20.113 35.424 20.797 35.448 ;
     RECT  20.761 34.08 20.905 34.104 ;
     RECT  20.797 35.424 20.905 36.36 ;
     RECT  20.117 3.024 21.085 3.048 ;
     RECT  20.581 17.088 21.085 18.744 ;
     RECT  20.905 34.08 21.085 36.36 ;
     RECT  20.581 37.44 21.085 39 ;
     RECT  20.545 31.584 21.121 32.04 ;
     RECT  19.897 20.592 21.157 22.536 ;
     RECT  20.509 23.712 21.157 24.552 ;
     RECT  21.121 31.584 21.157 32.76 ;
     RECT  20.333 40.848 21.157 40.968 ;
     RECT  19.043 43.104 21.233 43.128 ;
     RECT  21.085 2.832 21.308 3.048 ;
     RECT  19.523 5.088 21.308 5.112 ;
     RECT  20.933 6.24 21.308 6.264 ;
     RECT  20.581 7.632 21.308 7.656 ;
     RECT  20.869 9.504 21.308 9.528 ;
     RECT  20.509 10.704 21.308 10.968 ;
     RECT  20.221 11.952 21.308 13.56 ;
     RECT  20.941 14.832 21.308 14.856 ;
     RECT  21.085 16.896 21.308 18.744 ;
     RECT  21.157 20.592 21.308 24.552 ;
     RECT  19.757 25.632 21.308 26.568 ;
     RECT  18.904 28.992 21.308 29.16 ;
     RECT  19.955 30.192 21.308 30.216 ;
     RECT  21.157 31.584 21.308 33.096 ;
     RECT  21.085 34.08 21.308 39 ;
     RECT  21.157 39.984 21.308 40.968 ;
     RECT  21.308 2.148 21.412 41.052 ;
     RECT  21.412 2.418 21.604 40.782 ;
     RECT  21.604 6.864 21.665 13.128 ;
     RECT  21.604 20.592 21.665 21.192 ;
     RECT  21.665 6.864 21.731 11.64 ;
     RECT  21.731 6.864 21.772 8.664 ;
     RECT  21.604 3.936 21.773 3.96 ;
     RECT  21.772 6.864 21.773 8.472 ;
     RECT  21.604 16.896 21.773 18.84 ;
     RECT  21.773 6.864 21.827 6.888 ;
     RECT  21.731 10.272 21.923 11.64 ;
     RECT  21.665 13.104 21.953 13.128 ;
     RECT  21.604 22.752 21.953 27.24 ;
     RECT  21.604 14.16 21.989 14.184 ;
     RECT  21.665 20.592 21.989 21.144 ;
     RECT  21.604 28.416 22.097 29.64 ;
     RECT  21.773 16.896 22.205 18.456 ;
     RECT  21.953 24.48 22.259 27.24 ;
     RECT  21.923 10.272 22.313 11.448 ;
     RECT  22.313 11.424 22.385 11.448 ;
     RECT  21.953 22.752 22.421 23.448 ;
     RECT  22.259 25.104 22.421 27.24 ;
     RECT  21.604 31.296 22.457 33.048 ;
     RECT  22.457 31.296 22.547 32.856 ;
     RECT  22.547 31.776 22.745 32.856 ;
     RECT  22.745 31.776 22.781 32.328 ;
     RECT  22.421 25.44 22.896 27.24 ;
     RECT  22.205 17.616 23.245 17.64 ;
     RECT  22.097 29.616 23.425 29.64 ;
     RECT  23.245 17.616 23.497 17.688 ;
     RECT  23.101 12.528 23.533 12.552 ;
     RECT  23.497 17.04 23.641 17.688 ;
     RECT  23.353 19.344 23.713 19.368 ;
     RECT  21.604 38.976 23.749 39.096 ;
     RECT  21.773 8.448 23.785 8.472 ;
     RECT  21.604 15.456 23.785 15.48 ;
     RECT  22.313 10.272 23.797 10.296 ;
     RECT  23.641 16.848 23.857 17.688 ;
     RECT  21.989 20.592 23.857 21.048 ;
     RECT  23.353 22.032 23.857 22.056 ;
     RECT  23.797 10.272 23.893 10.872 ;
     RECT  23.857 16.56 23.893 17.688 ;
     RECT  23.713 18.72 23.893 19.368 ;
     RECT  23.533 12.528 23.929 13.128 ;
     RECT  23.785 7.968 24.008 8.472 ;
     RECT  23.893 10.272 24.008 11.16 ;
     RECT  23.929 12.528 24.008 13.368 ;
     RECT  23.785 15.264 24.008 15.48 ;
     RECT  23.893 16.56 24.008 19.368 ;
     RECT  23.857 20.592 24.008 22.056 ;
     RECT  22.421 23.424 24.008 23.448 ;
     RECT  22.896 25.44 24.008 26.904 ;
     RECT  22.097 28.416 24.008 28.44 ;
     RECT  23.425 29.616 24.008 30.168 ;
     RECT  22.781 31.776 24.008 31.8 ;
     RECT  21.604 34.08 24.008 34.104 ;
     RECT  21.604 35.664 24.008 37.464 ;
     RECT  23.749 38.976 24.008 39.96 ;
     RECT  24.008 2.148 24.112 41.052 ;
     RECT  24.112 2.418 24.304 40.824 ;
     RECT  24.304 16.848 24.725 16.92 ;
     RECT  24.304 29.376 24.797 30.168 ;
     RECT  24.304 14.88 24.905 15.288 ;
     RECT  24.304 7.824 24.941 8.184 ;
     RECT  24.304 10.704 25.013 11.4 ;
     RECT  24.304 20.592 25.013 22.824 ;
     RECT  24.304 26.784 25.049 27.672 ;
     RECT  24.304 6.24 25.091 6.744 ;
     RECT  24.941 7.824 25.091 7.848 ;
     RECT  24.304 38.88 25.091 40.824 ;
     RECT  24.757 0.528 25.225 0.552 ;
     RECT  24.304 18.528 25.333 19.368 ;
     RECT  25.333 18.192 25.337 19.368 ;
     RECT  25.013 20.592 25.337 21.144 ;
     RECT  24.304 31.776 25.373 33.048 ;
     RECT  25.013 11.136 25.381 11.4 ;
     RECT  24.304 12.528 25.381 12.552 ;
     RECT  25.337 18.192 25.381 18.84 ;
     RECT  25.381 11.136 25.427 13.32 ;
     RECT  24.905 14.88 25.427 14.904 ;
     RECT  25.427 13.296 25.468 13.32 ;
     RECT  24.725 16.896 25.477 16.92 ;
     RECT  25.381 18.192 25.477 18.216 ;
     RECT  24.304 36.336 25.517 37.464 ;
     RECT  25.517 36.576 25.553 37.464 ;
     RECT  25.427 11.136 25.661 12.264 ;
     RECT  25.477 16.896 25.733 18.216 ;
     RECT  25.553 36.912 25.765 37.464 ;
     RECT  25.091 38.88 25.765 40.296 ;
     RECT  25.225 0.384 26.053 0.552 ;
     RECT  25.049 27.312 26.053 27.672 ;
     RECT  24.797 29.376 26.053 29.4 ;
     RECT  25.013 22.8 26.089 22.824 ;
     RECT  24.304 9.552 26.108 9.576 ;
     RECT  25.765 36.912 26.125 40.296 ;
     RECT  25.733 16.896 26.161 17.112 ;
     RECT  25.837 20.4 26.161 20.424 ;
     RECT  26.089 22.032 26.233 22.824 ;
     RECT  24.304 25.392 26.377 25.56 ;
     RECT  26.053 0.384 26.485 1.128 ;
     RECT  25.693 2.256 26.485 2.28 ;
     RECT  26.161 20.016 26.521 20.424 ;
     RECT  26.521 20.016 26.549 20.616 ;
     RECT  25.373 31.776 26.549 32.52 ;
     RECT  26.485 0.384 26.708 2.28 ;
     RECT  25.091 6.24 26.708 6.264 ;
     RECT  26.108 8.88 26.708 9.576 ;
     RECT  25.661 11.136 26.708 11.16 ;
     RECT  25.661 12.24 26.708 12.264 ;
     RECT  25.729 13.68 26.708 13.704 ;
     RECT  26.161 16.848 26.708 17.112 ;
     RECT  25.733 18.192 26.708 18.216 ;
     RECT  26.549 19.92 26.708 20.616 ;
     RECT  26.233 22.032 26.708 23.064 ;
     RECT  26.377 25.392 26.708 25.704 ;
     RECT  26.053 27.312 26.708 29.4 ;
     RECT  26.549 31.248 26.708 32.52 ;
     RECT  25.873 34.128 26.708 34.152 ;
     RECT  26.125 36.912 26.708 40.44 ;
     RECT  26.708 0.384 26.812 41.052 ;
     RECT  26.812 0.384 27.004 40.872 ;
     RECT  27.004 0.384 27.059 2.28 ;
     RECT  27.004 36.912 27.101 40.872 ;
     RECT  27.004 21.696 27.155 23.544 ;
     RECT  27.004 20.16 27.173 20.616 ;
     RECT  27.004 13.056 27.209 15.24 ;
     RECT  27.004 25.296 27.299 34.248 ;
     RECT  27.059 0.528 27.347 2.28 ;
     RECT  27.004 6.24 27.388 7.08 ;
     RECT  27.347 1.68 27.443 2.28 ;
     RECT  27.299 25.296 27.635 28.488 ;
     RECT  27.004 18.24 27.731 18.84 ;
     RECT  27.155 21.696 27.749 21.72 ;
     RECT  27.101 38.16 27.749 40.872 ;
     RECT  27.635 25.296 27.857 27.288 ;
     RECT  27.857 25.296 27.868 25.848 ;
     RECT  27.155 22.8 27.916 23.544 ;
     RECT  27.443 2.208 27.923 2.28 ;
     RECT  27.749 38.16 27.965 40.44 ;
     RECT  27.004 9.552 28.031 9.672 ;
     RECT  27.004 11.76 28.037 11.976 ;
     RECT  27.388 7.056 28.069 7.08 ;
     RECT  28.031 9.552 28.069 10.536 ;
     RECT  27.299 32.208 28.076 34.248 ;
     RECT  27.004 35.568 28.076 35.592 ;
     RECT  27.101 36.912 28.076 37.08 ;
     RECT  27.347 0.528 28.115 0.552 ;
     RECT  28.076 32.208 28.117 34.536 ;
     RECT  28.076 35.568 28.117 37.08 ;
     RECT  27.857 27.264 28.145 27.288 ;
     RECT  28.117 32.208 28.145 37.08 ;
     RECT  27.965 38.976 28.145 40.44 ;
     RECT  28.145 34.512 28.163 37.08 ;
     RECT  27.209 13.056 28.213 14.28 ;
     RECT  28.069 15.696 28.213 15.72 ;
     RECT  27.299 30.096 28.268 30.936 ;
     RECT  28.145 32.208 28.268 33.096 ;
     RECT  28.163 36.528 28.289 37.08 ;
     RECT  28.213 13.056 28.307 15.72 ;
     RECT  28.268 30.096 28.355 33.096 ;
     RECT  27.173 20.16 28.357 20.424 ;
     RECT  27.916 22.8 28.429 23.304 ;
     RECT  27.731 18.672 28.501 18.84 ;
     RECT  27.635 28.416 28.637 28.488 ;
     RECT  27.004 16.848 28.645 16.92 ;
     RECT  28.357 20.16 28.789 21.144 ;
     RECT  28.786 0.096 28.876 0.264 ;
     RECT  28.876 0.096 28.909 0.12 ;
     RECT  27.923 2.256 28.978 2.28 ;
     RECT  28.355 30.096 29.077 32.52 ;
     RECT  28.978 2.208 29.408 2.28 ;
     RECT  28.069 7.056 29.408 7.416 ;
     RECT  28.069 8.88 29.408 10.536 ;
     RECT  28.037 11.952 29.408 11.976 ;
     RECT  28.307 13.056 29.408 13.992 ;
     RECT  28.307 15.696 29.408 15.72 ;
     RECT  28.645 16.848 29.408 17.256 ;
     RECT  28.501 18.672 29.408 19.128 ;
     RECT  28.789 20.16 29.408 21.672 ;
     RECT  28.429 22.752 29.408 23.304 ;
     RECT  28.529 24.528 29.408 24.552 ;
     RECT  27.868 25.728 29.408 25.848 ;
     RECT  28.637 28.32 29.408 28.488 ;
     RECT  29.077 29.808 29.408 32.52 ;
     RECT  28.163 35.28 29.408 35.304 ;
     RECT  28.289 36.528 29.408 37.032 ;
     RECT  28.145 38.976 29.408 39.528 ;
     RECT  29.408 2.148 29.512 41.052 ;
     RECT  29.512 2.418 29.704 40.782 ;
     RECT  29.704 38.976 30.733 39.528 ;
     RECT  30.733 38.976 30.769 39.624 ;
     RECT  30.769 38.784 30.881 39.624 ;
     RECT  30.881 38.976 32.321 39.12 ;
     RECT  30.881 39.12 32.316 39.144 ;
     RECT  30.881 39.144 32.321 39.216 ;
     RECT  30.881 39.216 32.316 39.24 ;
     RECT  30.881 39.24 32.321 39.312 ;
     RECT  30.881 39.312 32.316 39.336 ;
     RECT  30.881 39.336 32.321 39.408 ;
     RECT  30.881 39.408 32.316 39.432 ;
     RECT  30.881 39.432 32.321 39.504 ;
     RECT  30.881 39.504 32.316 39.528 ;
     RECT  30.881 39.528 32.321 39.6 ;
     RECT  30.881 39.6 32.316 39.624 ;
     RECT  32.321 39.144 32.364 39.216 ;
     RECT  32.321 39.24 32.364 39.312 ;
     RECT  32.321 39.336 32.364 39.408 ;
     RECT  32.321 39.432 32.364 39.504 ;
     RECT  32.321 39.528 32.364 39.6 ;
    LAYER M5 ;
     RECT  9.384 0.016 9.456 0.084 ;
     RECT  9.48 0.016 9.552 0.084 ;
     RECT  9.576 0.016 9.648 0.084 ;
     RECT  9.672 0.016 9.744 0.084 ;
     RECT  9.768 0.016 9.84 0.084 ;
     RECT  9.864 0.016 9.936 0.084 ;
     RECT  9.96 0.016 10.032 0.084 ;
     RECT  10.056 0.016 10.128 0.084 ;
     RECT  10.152 0.016 10.224 0.084 ;
     RECT  9.36 0.084 10.248 0.131 ;
     RECT  9.36 0.131 10.152 1.763 ;
     RECT  9.456 1.763 10.152 1.811 ;
     RECT  9.648 1.811 10.152 2.137 ;
     RECT  26.088 0.016 26.16 0.084 ;
     RECT  26.184 0.016 26.256 0.084 ;
     RECT  26.28 0.016 26.352 0.084 ;
     RECT  26.376 0.016 26.448 0.084 ;
     RECT  26.472 0.016 26.544 0.084 ;
     RECT  26.568 0.016 26.64 0.084 ;
     RECT  26.664 0.016 26.736 0.084 ;
     RECT  26.76 0.016 26.832 0.084 ;
     RECT  26.856 0.016 26.928 0.084 ;
     RECT  26.952 0.016 27.024 0.084 ;
     RECT  27.048 0.016 27.12 0.084 ;
     RECT  27.144 0.016 27.216 0.084 ;
     RECT  27.24 0.016 27.312 0.084 ;
     RECT  27.336 0.016 27.408 0.084 ;
     RECT  27.432 0.016 27.504 0.084 ;
     RECT  27.528 0.016 27.6 0.084 ;
     RECT  27.624 0.016 27.696 0.084 ;
     RECT  27.72 0.016 27.792 0.084 ;
     RECT  27.816 0.016 27.888 0.084 ;
     RECT  27.912 0.016 27.984 0.084 ;
     RECT  28.008 0.016 28.08 0.084 ;
     RECT  28.104 0.016 28.176 0.084 ;
     RECT  28.2 0.016 28.272 0.084 ;
     RECT  28.296 0.016 28.368 0.084 ;
     RECT  28.392 0.016 28.464 0.084 ;
     RECT  28.488 0.016 28.56 0.084 ;
     RECT  28.584 0.016 28.656 0.084 ;
     RECT  28.68 0.016 28.752 0.084 ;
     RECT  28.776 0.016 28.848 0.084 ;
     RECT  28.872 0.016 28.944 0.084 ;
     RECT  28.968 0.016 29.04 0.084 ;
     RECT  26.064 0.084 29.064 2.137 ;
     RECT  2.4 2.137 2.52 2.151 ;
     RECT  5.1 2.137 5.22 2.151 ;
     RECT  7.8 2.137 7.92 2.151 ;
     RECT  9.648 2.137 10.62 2.151 ;
     RECT  13.2 2.137 13.32 2.151 ;
     RECT  15.9 2.137 16.02 2.151 ;
     RECT  18.6 2.137 18.72 2.151 ;
     RECT  21.3 2.137 21.42 2.151 ;
     RECT  24 2.137 24.12 2.151 ;
     RECT  26.064 2.137 29.52 2.151 ;
     RECT  18.6 2.151 18.912 2.245 ;
     RECT  9.648 2.151 10.812 2.291 ;
     RECT  13.2 2.151 13.512 3.301 ;
     RECT  21.3 2.151 21.612 3.925 ;
     RECT  18.144 2.245 18.912 4.501 ;
     RECT  13.2 3.301 13.704 4.691 ;
     RECT  15.9 2.151 16.212 5.077 ;
     RECT  18.144 4.501 19.512 5.123 ;
     RECT  21.3 3.925 21.72 6.229 ;
     RECT  15.9 5.077 16.344 6.709 ;
     RECT  24 2.151 24.312 6.709 ;
     RECT  20.976 6.229 21.72 6.853 ;
     RECT  20.976 6.853 21.816 7.667 ;
     RECT  24 6.709 25.08 7.859 ;
     RECT  24 7.859 24.312 7.957 ;
     RECT  13.2 4.691 13.512 9.637 ;
     RECT  13.2 9.637 14.28 10.261 ;
     RECT  13.2 10.261 14.616 10.307 ;
     RECT  15.9 6.709 16.824 10.645 ;
     RECT  21.3 7.667 21.816 10.837 ;
     RECT  23.808 7.957 24.312 10.883 ;
     RECT  21.3 10.837 21.864 11.413 ;
     RECT  14.592 10.307 14.616 11.459 ;
     RECT  15.9 10.645 16.968 11.509 ;
     RECT  15.792 11.509 16.968 11.555 ;
     RECT  21.3 11.413 21.912 11.651 ;
     RECT  5.1 2.151 5.412 11.941 ;
     RECT  26.064 2.151 29.712 11.941 ;
     RECT  4.272 11.941 5.412 12.229 ;
     RECT  21.3 11.651 21.72 12.325 ;
     RECT  4.272 12.229 5.88 12.373 ;
     RECT  23.904 10.883 24.312 12.517 ;
     RECT  3.888 12.373 5.88 12.563 ;
     RECT  15.792 11.555 16.824 12.851 ;
     RECT  15.9 12.851 16.824 12.997 ;
     RECT  18.144 5.123 18.912 12.997 ;
     RECT  15.9 12.997 18.912 13.045 ;
     RECT  13.2 10.307 13.512 13.093 ;
     RECT  9.84 2.291 10.812 13.139 ;
     RECT  23.568 12.517 24.312 13.139 ;
     RECT  20.592 12.325 21.72 13.331 ;
     RECT  5.1 12.563 5.88 13.477 ;
     RECT  5.1 13.477 6.408 13.525 ;
     RECT  7.8 2.151 8.112 13.525 ;
     RECT  5.1 13.525 8.112 13.573 ;
     RECT  2.4 2.151 2.712 13.957 ;
     RECT  3.888 12.563 3.912 13.957 ;
     RECT  15.9 13.045 19.32 14.195 ;
     RECT  2.4 13.957 3.912 14.197 ;
     RECT  4.944 13.573 8.112 14.197 ;
     RECT  15.9 14.195 16.728 14.197 ;
     RECT  13.104 13.093 13.512 14.867 ;
     RECT  25.392 11.941 29.712 14.915 ;
     RECT  14.976 14.197 16.728 15.443 ;
     RECT  2.4 14.197 8.112 15.491 ;
     RECT  3.744 15.491 8.112 15.829 ;
     RECT  13.2 14.867 13.512 16.261 ;
     RECT  3.744 15.829 8.472 16.981 ;
     RECT  10.128 13.139 10.812 16.981 ;
     RECT  21.3 13.331 21.72 17.077 ;
     RECT  13.104 16.261 13.512 17.123 ;
     RECT  26.352 14.915 29.712 17.123 ;
     RECT  20.592 17.077 21.72 17.459 ;
     RECT  3.744 16.981 10.812 17.557 ;
     RECT  18.144 14.195 19.32 17.605 ;
     RECT  3.744 17.557 11.064 17.651 ;
     RECT  13.2 17.123 13.512 18.181 ;
     RECT  23.904 13.139 24.312 18.275 ;
     RECT  15.9 15.443 16.728 18.565 ;
     RECT  25.344 18.181 25.368 18.851 ;
     RECT  9.648 17.651 11.064 19.333 ;
     RECT  9.648 19.333 11.256 20.003 ;
     RECT  13.008 18.181 13.512 20.291 ;
     RECT  18.144 17.605 19.512 20.291 ;
     RECT  9.648 20.003 10.812 20.339 ;
     RECT  15.792 18.565 16.728 20.773 ;
     RECT  18.144 20.291 19.32 20.773 ;
     RECT  15.792 20.773 19.32 21.011 ;
     RECT  13.2 20.291 13.512 21.061 ;
     RECT  15.9 21.011 19.32 21.107 ;
     RECT  10.128 20.339 10.812 21.539 ;
     RECT  10.5 21.539 10.812 21.637 ;
     RECT  10.5 21.637 12.12 21.779 ;
     RECT  13.2 21.061 14.28 22.067 ;
     RECT  18.144 21.107 19.32 22.069 ;
     RECT  21.3 17.459 21.72 22.069 ;
     RECT  15.9 21.107 16.632 22.597 ;
     RECT  20.688 22.069 21.72 23.317 ;
     RECT  20.688 23.317 22.248 23.701 ;
     RECT  2.4 15.491 2.712 23.845 ;
     RECT  3.744 17.651 8.472 23.845 ;
     RECT  12.096 21.779 12.12 23.845 ;
     RECT  13.2 22.067 13.512 23.845 ;
     RECT  17.952 22.069 19.32 23.987 ;
     RECT  15.552 22.597 16.632 24.515 ;
     RECT  20.544 23.701 22.248 24.563 ;
     RECT  12.096 23.845 13.512 25.139 ;
     RECT  21.3 24.563 22.248 25.139 ;
     RECT  15.792 24.515 16.632 25.715 ;
     RECT  26.544 17.123 29.712 25.715 ;
     RECT  10.5 21.779 10.812 26.533 ;
     RECT  2.4 23.845 8.472 26.629 ;
     RECT  10.368 26.533 10.812 26.771 ;
     RECT  13.2 25.139 13.512 26.773 ;
     RECT  15.9 25.715 16.632 26.869 ;
     RECT  2.4 26.629 8.52 27.205 ;
     RECT  13.2 26.773 14.232 27.347 ;
     RECT  18.144 23.987 19.32 27.781 ;
     RECT  10.5 26.771 10.812 27.877 ;
     RECT  12.096 25.139 12.12 27.877 ;
     RECT  26.7 25.715 29.712 27.877 ;
     RECT  26.16 27.877 29.712 27.971 ;
     RECT  22.8 27.205 22.824 28.451 ;
     RECT  10.5 27.877 12.12 28.547 ;
     RECT  26.16 27.971 27.288 28.547 ;
     RECT  15.9 26.869 16.776 28.693 ;
     RECT  21.3 25.139 21.72 28.787 ;
     RECT  18.144 27.781 19.992 28.981 ;
     RECT  21.3 28.787 21.612 28.981 ;
     RECT  18.144 28.981 21.612 29.027 ;
     RECT  12.096 28.547 12.12 29.173 ;
     RECT  12.096 29.173 12.216 29.219 ;
     RECT  2.4 27.205 8.568 29.363 ;
     RECT  15.9 28.693 16.968 29.699 ;
     RECT  18.144 29.027 19.32 30.181 ;
     RECT  20.496 29.027 21.612 30.181 ;
     RECT  18.144 30.181 21.612 30.227 ;
     RECT  26.7 28.547 27.288 30.229 ;
     RECT  28.368 27.971 29.712 30.229 ;
     RECT  26.7 30.229 29.712 30.947 ;
     RECT  26.7 30.947 27.288 31.237 ;
     RECT  21.3 30.227 21.612 31.285 ;
     RECT  15.9 29.699 16.728 31.619 ;
     RECT  26.592 31.237 27.288 31.811 ;
     RECT  18.144 30.227 19.944 31.861 ;
     RECT  21.3 31.285 22.536 31.861 ;
     RECT  24 18.275 24.312 31.861 ;
     RECT  2.4 29.363 8.472 31.955 ;
     RECT  26.592 31.811 27.24 31.955 ;
     RECT  28.32 30.947 29.712 31.955 ;
     RECT  18.144 31.861 22.536 32.339 ;
     RECT  2.4 31.955 8.28 32.437 ;
     RECT  12.192 29.219 12.216 32.437 ;
     RECT  13.2 27.347 13.512 32.437 ;
     RECT  18.144 32.339 21.912 32.437 ;
     RECT  2.304 32.437 8.28 32.531 ;
     RECT  26.592 31.955 27.144 32.531 ;
     RECT  17.952 32.437 21.912 33.011 ;
     RECT  15.9 31.619 16.212 33.013 ;
     RECT  24 31.861 24.936 33.059 ;
     RECT  28.32 31.955 28.344 33.107 ;
     RECT  15.9 33.013 16.344 34.067 ;
     RECT  2.304 32.531 8.112 34.117 ;
     RECT  12.192 32.437 13.512 34.211 ;
     RECT  2.304 34.117 8.712 34.259 ;
     RECT  17.952 33.011 19.32 34.259 ;
     RECT  26.7 32.531 27.144 34.259 ;
     RECT  2.4 34.259 8.712 34.835 ;
     RECT  12.192 34.211 12.216 34.835 ;
     RECT  14.784 31.525 14.808 34.931 ;
     RECT  7.488 34.835 8.712 35.173 ;
     RECT  2.4 34.835 6.408 35.363 ;
     RECT  2.4 35.363 5.928 35.459 ;
     RECT  2.4 35.459 3.768 35.939 ;
     RECT  4.752 35.459 5.928 35.939 ;
     RECT  20.496 33.011 21.912 35.939 ;
     RECT  24 33.059 24.312 36.085 ;
     RECT  2.4 35.939 3.24 36.515 ;
     RECT  4.944 35.939 5.928 36.515 ;
     RECT  5.1 36.515 5.928 36.563 ;
     RECT  15.9 34.067 16.212 36.997 ;
     RECT  28.128 34.501 28.152 37.043 ;
     RECT  5.1 36.563 5.784 37.091 ;
     RECT  23.04 36.085 24.312 37.331 ;
     RECT  7.488 35.173 9.24 37.429 ;
     RECT  13.2 34.211 13.512 37.429 ;
     RECT  20.496 35.939 21.612 37.667 ;
     RECT  2.4 36.515 2.712 38.149 ;
     RECT  6.816 37.429 9.24 38.149 ;
     RECT  10.5 28.547 10.812 38.149 ;
     RECT  15.9 36.997 16.392 38.149 ;
     RECT  18.24 34.259 19.32 38.149 ;
     RECT  6.816 38.149 10.812 38.195 ;
     RECT  18.096 38.149 19.32 38.197 ;
     RECT  6.816 38.195 8.568 38.387 ;
     RECT  5.1 37.091 5.688 38.677 ;
     RECT  9.552 38.195 10.812 38.677 ;
     RECT  12.72 37.429 13.512 38.725 ;
     RECT  7.8 38.387 8.568 38.819 ;
     RECT  17.424 38.197 19.32 38.819 ;
     RECT  9.552 38.677 11.112 39.059 ;
     RECT  2.4 38.149 3.24 39.251 ;
     RECT  25.488 39.061 25.512 39.491 ;
     RECT  15.9 38.149 16.44 39.685 ;
     RECT  17.424 38.819 18.912 39.685 ;
     RECT  5.1 38.677 6.312 39.829 ;
     RECT  23.76 37.331 24.312 39.829 ;
     RECT  4.848 39.829 6.312 39.877 ;
     RECT  9.552 39.059 10.812 39.923 ;
     RECT  23.76 39.829 25.08 39.971 ;
     RECT  21.168 37.667 21.612 40.019 ;
     RECT  12.72 38.725 14.232 40.067 ;
     RECT  13.2 40.067 14.232 40.405 ;
     RECT  13.2 40.405 14.28 40.453 ;
     RECT  13.2 40.453 14.76 40.549 ;
     RECT  15.9 39.685 18.912 40.549 ;
     RECT  13.2 40.549 18.912 40.789 ;
     RECT  24 39.971 25.08 40.835 ;
     RECT  4.656 39.877 6.312 40.933 ;
     RECT  2.4 39.251 2.712 40.981 ;
     RECT  4.464 40.933 6.312 40.981 ;
     RECT  2.4 40.981 3.336 41.029 ;
     RECT  4.368 40.981 6.312 41.029 ;
     RECT  7.8 38.819 8.112 41.049 ;
     RECT  10.5 39.923 10.812 41.049 ;
     RECT  21.3 40.019 21.612 41.049 ;
     RECT  24 40.835 24.312 41.049 ;
     RECT  26.7 34.259 27.012 41.049 ;
     RECT  29.4 31.955 29.712 41.049 ;
     RECT  2.4 41.029 6.312 41.063 ;
     RECT  7.8 41.049 7.92 41.063 ;
     RECT  10.5 41.049 10.62 41.063 ;
     RECT  13.2 40.789 19.368 41.063 ;
     RECT  21.3 41.049 21.42 41.063 ;
     RECT  24 41.049 24.12 41.063 ;
     RECT  26.7 41.049 26.82 41.063 ;
     RECT  29.4 41.049 29.52 41.063 ;
     RECT  3.312 41.063 6.312 43.116 ;
     RECT  3.336 43.116 3.408 43.152 ;
     RECT  3.432 43.116 3.504 43.152 ;
     RECT  3.528 43.116 3.6 43.152 ;
     RECT  3.624 43.116 3.696 43.152 ;
     RECT  3.72 43.116 3.792 43.152 ;
     RECT  3.816 43.116 3.888 43.152 ;
     RECT  3.912 43.116 3.984 43.152 ;
     RECT  4.008 43.116 4.08 43.152 ;
     RECT  4.104 43.116 4.176 43.152 ;
     RECT  4.2 43.116 4.272 43.152 ;
     RECT  4.296 43.116 4.368 43.152 ;
     RECT  4.392 43.116 4.464 43.152 ;
     RECT  4.488 43.116 4.56 43.152 ;
     RECT  4.584 43.116 4.656 43.152 ;
     RECT  4.68 43.116 4.752 43.152 ;
     RECT  4.776 43.116 4.848 43.152 ;
     RECT  4.872 43.116 4.944 43.152 ;
     RECT  4.968 43.116 5.04 43.152 ;
     RECT  5.064 43.116 5.136 43.152 ;
     RECT  5.16 43.116 5.232 43.152 ;
     RECT  5.256 43.116 5.328 43.152 ;
     RECT  5.352 43.116 5.424 43.152 ;
     RECT  5.448 43.116 5.52 43.152 ;
     RECT  5.544 43.116 5.616 43.152 ;
     RECT  5.64 43.116 5.712 43.152 ;
     RECT  5.736 43.116 5.808 43.152 ;
     RECT  5.832 43.116 5.904 43.152 ;
     RECT  5.928 43.116 6 43.152 ;
     RECT  6.024 43.116 6.096 43.152 ;
     RECT  6.12 43.116 6.192 43.152 ;
     RECT  6.216 43.116 6.288 43.152 ;
     RECT  13.296 41.063 19.368 43.116 ;
     RECT  13.32 43.116 13.392 43.152 ;
     RECT  13.416 43.116 13.488 43.152 ;
     RECT  13.512 43.116 13.584 43.152 ;
     RECT  13.608 43.116 13.68 43.152 ;
     RECT  13.704 43.116 13.776 43.152 ;
     RECT  13.8 43.116 13.872 43.152 ;
     RECT  13.896 43.116 13.968 43.152 ;
     RECT  13.992 43.116 14.064 43.152 ;
     RECT  14.088 43.116 14.16 43.152 ;
     RECT  14.184 43.116 14.256 43.152 ;
     RECT  14.28 43.116 14.352 43.152 ;
     RECT  14.376 43.116 14.448 43.152 ;
     RECT  14.472 43.116 14.544 43.152 ;
     RECT  14.568 43.116 14.64 43.152 ;
     RECT  14.664 43.116 14.736 43.152 ;
     RECT  14.76 43.116 14.832 43.152 ;
     RECT  14.856 43.116 14.928 43.152 ;
     RECT  14.952 43.116 15.024 43.152 ;
     RECT  15.048 43.116 15.12 43.152 ;
     RECT  15.144 43.116 15.216 43.152 ;
     RECT  15.24 43.116 15.312 43.152 ;
     RECT  15.336 43.116 15.408 43.152 ;
     RECT  15.432 43.116 15.504 43.152 ;
     RECT  15.528 43.116 15.6 43.152 ;
     RECT  15.624 43.116 15.696 43.152 ;
     RECT  15.72 43.116 15.792 43.152 ;
     RECT  15.816 43.116 15.888 43.152 ;
     RECT  15.912 43.116 15.984 43.152 ;
     RECT  16.008 43.116 16.08 43.152 ;
     RECT  16.104 43.116 16.176 43.152 ;
     RECT  16.2 43.116 16.272 43.152 ;
     RECT  16.296 43.116 16.368 43.152 ;
     RECT  16.392 43.116 16.464 43.152 ;
     RECT  16.488 43.116 16.56 43.152 ;
     RECT  16.584 43.116 16.656 43.152 ;
     RECT  16.68 43.116 16.752 43.152 ;
     RECT  16.776 43.116 16.848 43.152 ;
     RECT  16.872 43.116 16.944 43.152 ;
     RECT  16.968 43.116 17.04 43.152 ;
     RECT  17.064 43.116 17.136 43.152 ;
     RECT  17.16 43.116 17.232 43.152 ;
     RECT  17.256 43.116 17.328 43.152 ;
     RECT  17.352 43.116 17.424 43.152 ;
     RECT  17.448 43.116 17.52 43.152 ;
     RECT  17.544 43.116 17.616 43.152 ;
     RECT  17.64 43.116 17.712 43.152 ;
     RECT  17.736 43.116 17.808 43.152 ;
     RECT  17.832 43.116 17.904 43.152 ;
     RECT  17.928 43.116 18 43.152 ;
     RECT  18.024 43.116 18.096 43.152 ;
     RECT  18.12 43.116 18.192 43.152 ;
     RECT  18.216 43.116 18.288 43.152 ;
     RECT  18.312 43.116 18.384 43.152 ;
     RECT  18.408 43.116 18.48 43.152 ;
     RECT  18.504 43.116 18.576 43.152 ;
     RECT  18.6 43.116 18.672 43.152 ;
     RECT  18.696 43.116 18.768 43.152 ;
     RECT  18.792 43.116 18.864 43.152 ;
     RECT  18.888 43.116 18.96 43.152 ;
     RECT  18.984 43.116 19.056 43.152 ;
     RECT  19.08 43.116 19.152 43.152 ;
     RECT  19.176 43.116 19.248 43.152 ;
     RECT  19.272 43.116 19.344 43.152 ;
     RECT  16.824 6.709 18.144 10.645 ;
     RECT  25.08 6.709 26.064 7.859 ;
     RECT  14.616 10.261 15.9 11.459 ;
     RECT  13.512 10.307 14.592 11.459 ;
     RECT  16.968 10.645 18.144 11.555 ;
     RECT  15.792 11.459 15.9 11.509 ;
     RECT  16.824 11.555 18.144 12.997 ;
     RECT  24.312 11.941 25.392 14.915 ;
     RECT  2.712 12.373 3.888 13.957 ;
     RECT  3.912 12.563 5.1 13.573 ;
     RECT  15.792 12.851 15.9 14.197 ;
     RECT  19.32 13.045 20.592 13.331 ;
     RECT  6.408 13.477 7.8 13.525 ;
     RECT  3.912 13.573 4.944 14.197 ;
     RECT  16.728 14.195 18.144 20.773 ;
     RECT  13.512 14.197 14.976 15.443 ;
     RECT  13.104 14.867 13.2 16.261 ;
     RECT  2.712 15.491 3.744 23.845 ;
     RECT  19.32 17.077 20.592 17.459 ;
     RECT  13.104 17.123 13.2 18.181 ;
     RECT  26.352 17.123 26.544 18.181 ;
     RECT  19.32 17.459 19.512 17.605 ;
     RECT  8.472 17.651 9.648 20.339 ;
     RECT  24.312 18.181 25.344 18.851 ;
     RECT  25.368 18.181 26.544 18.851 ;
     RECT  13.008 20.291 13.2 21.637 ;
     RECT  16.632 21.107 18.144 22.069 ;
     RECT  12.12 21.637 13.2 23.845 ;
     RECT  10.812 21.779 12.096 27.877 ;
     RECT  16.632 22.069 17.952 23.987 ;
     RECT  19.32 22.069 20.688 23.701 ;
     RECT  19.32 23.701 20.544 24.563 ;
     RECT  16.632 23.987 18.144 26.869 ;
     RECT  12.12 25.139 13.2 29.173 ;
     RECT  16.776 26.869 18.144 28.693 ;
     RECT  21.72 27.205 22.8 28.451 ;
     RECT  22.824 27.205 24 28.451 ;
     RECT  19.992 27.781 21.3 28.981 ;
     RECT  27.288 27.971 28.368 30.229 ;
     RECT  10.812 28.547 12.096 29.219 ;
     RECT  16.968 28.693 18.144 29.699 ;
     RECT  19.32 29.027 20.496 30.181 ;
     RECT  12.216 29.173 13.2 32.437 ;
     RECT  10.812 29.219 12.192 34.835 ;
     RECT  16.728 29.699 18.144 31.619 ;
     RECT  19.944 30.227 21.3 31.861 ;
     RECT  27.288 30.947 28.32 31.811 ;
     RECT  22.536 31.285 24 32.339 ;
     RECT  13.512 31.525 14.784 34.931 ;
     RECT  14.808 31.525 15.9 34.931 ;
     RECT  16.212 31.619 16.344 33.013 ;
     RECT  17.952 31.619 18.144 32.437 ;
     RECT  27.24 31.811 28.32 31.955 ;
     RECT  27.144 31.955 28.32 33.107 ;
     RECT  28.344 31.955 29.4 33.107 ;
     RECT  19.32 33.011 20.496 37.667 ;
     RECT  27.144 33.107 29.4 34.259 ;
     RECT  12.216 34.211 13.2 34.835 ;
     RECT  27.012 34.259 29.4 34.501 ;
     RECT  27.012 34.501 28.128 37.043 ;
     RECT  28.152 34.501 29.4 37.043 ;
     RECT  6.408 34.835 7.488 35.363 ;
     RECT  9.24 35.173 10.5 38.149 ;
     RECT  3.768 35.459 4.752 35.939 ;
     RECT  21.612 35.939 21.912 36.085 ;
     RECT  21.612 36.085 23.04 37.331 ;
     RECT  5.784 36.563 5.928 37.091 ;
     RECT  5.688 37.091 5.928 37.429 ;
     RECT  5.688 37.429 6.816 38.387 ;
     RECT  8.568 38.195 9.552 38.819 ;
     RECT  16.44 38.197 17.424 39.685 ;
     RECT  5.688 38.387 7.8 38.677 ;
     RECT  6.312 38.677 7.8 41.063 ;
     RECT  8.112 38.819 9.552 39.923 ;
     RECT  24.312 39.061 25.488 39.491 ;
     RECT  25.512 39.061 26.7 39.491 ;
     RECT  24.312 39.491 25.08 39.829 ;
     RECT  14.76 40.453 15.9 40.549 ;
     RECT  3.336 40.981 4.368 41.029 ;
  END
END hbfd_land_136_SN
END LIBRARY
